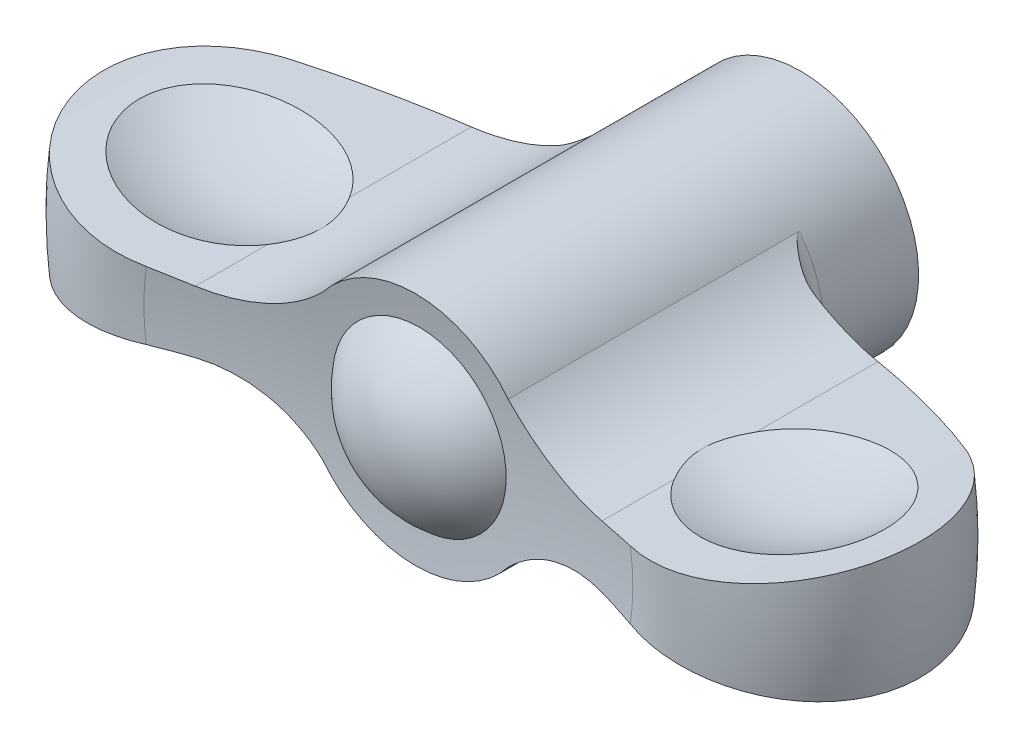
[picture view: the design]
ISO-10303-21;
HEADER;
FILE_DESCRIPTION(('STEP AP214'),'2;1');
FILE_NAME('part.step','',(''),(''),'','','');
FILE_SCHEMA(('AUTOMOTIVE_DESIGN { 1 0 10303 214 1 1 1 1 }'));
ENDSEC;
DATA;
#1=APPLICATION_CONTEXT('core data for automotive mechanical design processes');
#2=APPLICATION_PROTOCOL_DEFINITION('international standard','automotive_design',2000,#1);
#3=PRODUCT_CONTEXT('',#1,'mechanical');
#4=PRODUCT('Part','Part','',(#3));
#5=PRODUCT_RELATED_PRODUCT_CATEGORY('part','',(#4));
#6=PRODUCT_DEFINITION_FORMATION('','',#4);
#7=PRODUCT_DEFINITION_CONTEXT('part definition',#1,'design');
#8=PRODUCT_DEFINITION('design','',#6,#7);
#9=PRODUCT_DEFINITION_SHAPE('','',#8);
#10=(LENGTH_UNIT() NAMED_UNIT(*) SI_UNIT(.MILLI.,.METRE.));
#11=(NAMED_UNIT(*) PLANE_ANGLE_UNIT() SI_UNIT($,.RADIAN.));
#12=(NAMED_UNIT(*) SI_UNIT($,.STERADIAN.) SOLID_ANGLE_UNIT());
#13=UNCERTAINTY_MEASURE_WITH_UNIT(LENGTH_MEASURE(1.E-05),#10,'distance_accuracy_value','');
#14=(GEOMETRIC_REPRESENTATION_CONTEXT(3) GLOBAL_UNCERTAINTY_ASSIGNED_CONTEXT((#13)) GLOBAL_UNIT_ASSIGNED_CONTEXT((#10,
#11,#12)) REPRESENTATION_CONTEXT('',''));
#15=CARTESIAN_POINT('',(0.,0.,0.));
#16=DIRECTION('',(0.,0.,1.));
#17=DIRECTION('',(1.,0.,0.));
#18=AXIS2_PLACEMENT_3D('',#15,#16,#17);
#19=CARTESIAN_POINT('',(0.,0.,8.));
#20=DIRECTION('',(0.,0.,-1.));
#21=DIRECTION('',(0.,1.,0.));
#22=AXIS2_PLACEMENT_3D('',#19,#20,#21);
#23=TOROIDAL_SURFACE('',#22,11.8,1.80000000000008);
#24=CARTESIAN_POINT('',(-10.936400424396,-3.94636818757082,9.7916319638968));
#25=CARTESIAN_POINT('',(-10.824118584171,-4.00370429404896,9.78325234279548));
#26=CARTESIAN_POINT('',(-10.7132133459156,-4.06254400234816,9.76897182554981));
#27=CARTESIAN_POINT('',(-10.4947965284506,-4.18269546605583,9.73031315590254));
#28=CARTESIAN_POINT('',(-10.3872790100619,-4.24400241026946,9.70595387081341));
#29=CARTESIAN_POINT('',(-10.1765147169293,-4.36838152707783,9.6489761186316));
#30=CARTESIAN_POINT('',(-10.0732455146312,-4.43144032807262,9.61641003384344));
#31=CARTESIAN_POINT('',(-9.87034998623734,-4.55941800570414,9.54423053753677));
#32=CARTESIAN_POINT('',(-9.77072514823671,-4.62433762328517,9.50461428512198));
#33=CARTESIAN_POINT('',(-9.55076497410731,-4.77218804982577,9.40879869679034));
#34=CARTESIAN_POINT('',(-9.43146470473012,-4.85557105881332,9.35092807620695));
#35=CARTESIAN_POINT('',(-9.19845422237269,-5.0245357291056,9.22749490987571));
#36=CARTESIAN_POINT('',(-9.08474708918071,-5.11011856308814,9.16192819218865));
#37=CARTESIAN_POINT('',(-8.89583509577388,-5.25740071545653,9.04459290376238));
#38=CARTESIAN_POINT('',(-8.81922141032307,-5.31864764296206,8.99450670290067));
#39=CARTESIAN_POINT('',(-8.66877804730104,-5.44185241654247,8.89113944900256));
#40=CARTESIAN_POINT('',(-8.59494804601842,-5.50381017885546,8.83785876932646));
#41=CARTESIAN_POINT('',(-8.4741799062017,-5.60755853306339,8.74594898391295));
#42=CARTESIAN_POINT('',(-8.42641392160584,-5.64925103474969,8.7082931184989));
#43=CARTESIAN_POINT('',(-8.33242521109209,-5.73256077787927,8.6310972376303));
#44=CARTESIAN_POINT('',(-8.28620142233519,-5.77417805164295,8.59155856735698));
#45=CARTESIAN_POINT('',(-8.21125367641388,-5.84266935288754,8.52388347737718));
#46=CARTESIAN_POINT('',(-8.18198002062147,-5.86968993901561,8.49650386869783));
#47=CARTESIAN_POINT('',(-8.12444979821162,-5.92330159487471,8.44010631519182));
#48=CARTESIAN_POINT('',(-8.09619524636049,-5.94989176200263,8.41108538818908));
#49=CARTESIAN_POINT('',(-8.04234032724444,-6.00103726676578,8.35179046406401));
#50=CARTESIAN_POINT('',(-8.01668026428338,-6.02563150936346,8.32160361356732));
#51=CARTESIAN_POINT('',(-7.96790958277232,-6.07276025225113,8.2576023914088));
#52=CARTESIAN_POINT('',(-7.94479257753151,-6.09529988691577,8.22379754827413));
#53=CARTESIAN_POINT('',(-7.91701322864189,-6.12255630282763,8.17250880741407));
#54=CARTESIAN_POINT('',(-7.90975258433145,-6.12970126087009,8.157793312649));
#55=CARTESIAN_POINT('',(-7.89665438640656,-6.14261741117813,8.12727584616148));
#56=CARTESIAN_POINT('',(-7.89080740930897,-6.14839769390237,8.11148202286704));
#57=CARTESIAN_POINT('',(-7.88158226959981,-6.15753000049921,8.08013275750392));
#58=CARTESIAN_POINT('',(-7.87802903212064,-6.16105398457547,8.06468423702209));
#59=CARTESIAN_POINT('',(-7.87307566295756,-6.16597001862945,8.03281428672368));
#60=CARTESIAN_POINT('',(-7.87172008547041,-6.16731795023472,8.01637956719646));
#61=CARTESIAN_POINT('',(-7.8717856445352,-6.16725149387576,7.9998));
#62=B_SPLINE_CURVE_WITH_KNOTS('',3,(#24,#25,#26,#27,#28,#29,#30,#31,#32,#33,#34,#35,#36,#37,#38,
#39,#40,#41,#42,#43,#44,#45,#46,#47,#48,#49,#50,#51,#52,#53,#54,#55,#56,#57,#58,#59,#60,#61),
.UNSPECIFIED.,.F.,.F.,(4,2,2,2,2,2,2,2,2,2,2,2,2,2,2,2,2,2,4),(0.,0.378686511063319,
0.756667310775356,1.13229407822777,1.50807255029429,1.97761636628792,2.44741590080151,
2.77774393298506,3.10803343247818,3.32923096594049,3.55027276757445,3.6952714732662,
3.84054267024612,3.98039395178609,4.11988557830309,4.17347981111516,4.22670627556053,
4.27513325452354,4.32453026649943),.UNSPECIFIED.);
#63=CARTESIAN_POINT('',(-10.9337221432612,-3.94773654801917,9.7914319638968));
#64=VERTEX_POINT('',#63);
#65=CARTESIAN_POINT('',(-7.8717855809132,-6.16725155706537,8.));
#66=VERTEX_POINT('',#65);
#67=EDGE_CURVE('E487',#64,#66,#62,.T.);
#68=ORIENTED_EDGE('',*,*,#67,.F.);
#69=CARTESIAN_POINT('',(0.,0.,9.7914319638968));
#70=DIRECTION('',(0.,0.,-1.));
#71=DIRECTION('',(0.,1.,0.));
#72=AXIS2_PLACEMENT_3D('',#69,#70,#71);
#73=CIRCLE('',#72,11.6245818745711);
#74=CARTESIAN_POINT('',(-10.9337221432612,3.94773654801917,9.7914319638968));
#75=VERTEX_POINT('',#74);
#76=EDGE_CURVE('E500',#64,#75,#73,.T.);
#77=ORIENTED_EDGE('',*,*,#76,.T.);
#78=CARTESIAN_POINT('',(-10.936400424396,3.94636818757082,9.7916319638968));
#79=CARTESIAN_POINT('',(-10.824118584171,4.00370429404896,9.78325234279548));
#80=CARTESIAN_POINT('',(-10.7132133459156,4.06254400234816,9.76897182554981));
#81=CARTESIAN_POINT('',(-10.4947965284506,4.18269546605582,9.73031315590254));
#82=CARTESIAN_POINT('',(-10.3872790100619,4.24400241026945,9.70595387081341));
#83=CARTESIAN_POINT('',(-10.1765147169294,4.36838152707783,9.64897611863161));
#84=CARTESIAN_POINT('',(-10.0732455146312,4.43144032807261,9.61641003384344));
#85=CARTESIAN_POINT('',(-9.87034998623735,4.55941800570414,9.54423053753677));
#86=CARTESIAN_POINT('',(-9.77072514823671,4.62433762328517,9.50461428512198));
#87=CARTESIAN_POINT('',(-9.55076497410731,4.77218804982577,9.40879869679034));
#88=CARTESIAN_POINT('',(-9.43146470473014,4.85557105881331,9.35092807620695));
#89=CARTESIAN_POINT('',(-9.1984542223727,5.02453572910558,9.22749490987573));
#90=CARTESIAN_POINT('',(-9.0847470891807,5.11011856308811,9.1619281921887));
#91=CARTESIAN_POINT('',(-8.89583509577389,5.25740071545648,9.04459290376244));
#92=CARTESIAN_POINT('',(-8.8192214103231,5.318647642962,8.99450670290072));
#93=CARTESIAN_POINT('',(-8.66877804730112,5.44185241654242,8.89113944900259));
#94=CARTESIAN_POINT('',(-8.59494804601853,5.50381017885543,8.8378587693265));
#95=CARTESIAN_POINT('',(-8.47417990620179,5.60755853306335,8.74594898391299));
#96=CARTESIAN_POINT('',(-8.4264139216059,5.64925103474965,8.70829311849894));
#97=CARTESIAN_POINT('',(-8.33242521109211,5.73256077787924,8.63109723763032));
#98=CARTESIAN_POINT('',(-8.2862014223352,5.77417805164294,8.59155856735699));
#99=CARTESIAN_POINT('',(-8.21125367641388,5.84266935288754,8.52388347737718));
#100=CARTESIAN_POINT('',(-8.18198002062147,5.86968993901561,8.49650386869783));
#101=CARTESIAN_POINT('',(-8.12444979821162,5.92330159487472,8.44010631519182));
#102=CARTESIAN_POINT('',(-8.09619524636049,5.94989176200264,8.41108538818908));
#103=CARTESIAN_POINT('',(-8.04234032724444,6.00103726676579,8.35179046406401));
#104=CARTESIAN_POINT('',(-8.01668026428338,6.02563150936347,8.32160361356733));
#105=CARTESIAN_POINT('',(-7.96790958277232,6.07276025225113,8.2576023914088));
#106=CARTESIAN_POINT('',(-7.94479257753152,6.09529988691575,8.22379754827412));
#107=CARTESIAN_POINT('',(-7.91701322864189,6.12255630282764,8.17250880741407));
#108=CARTESIAN_POINT('',(-7.90975258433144,6.1297012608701,8.15779331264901));
#109=CARTESIAN_POINT('',(-7.89665438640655,6.14261741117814,8.12727584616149));
#110=CARTESIAN_POINT('',(-7.89080740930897,6.14839769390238,8.11148202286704));
#111=CARTESIAN_POINT('',(-7.88158226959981,6.1575300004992,8.08013275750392));
#112=CARTESIAN_POINT('',(-7.87802903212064,6.16105398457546,8.06468423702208));
#113=CARTESIAN_POINT('',(-7.87307566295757,6.16597001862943,8.03281428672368));
#114=CARTESIAN_POINT('',(-7.87172008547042,6.16731795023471,8.01637956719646));
#115=CARTESIAN_POINT('',(-7.8717856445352,6.16725149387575,7.9998));
#116=B_SPLINE_CURVE_WITH_KNOTS('',3,(#78,#79,#80,#81,#82,#83,#84,#85,#86,#87,#88,#89,#90,#91,
#92,#93,#94,#95,#96,#97,#98,#99,#100,#101,#102,#103,#104,#105,#106,#107,#108,#109,#110,#111,
#112,#113,#114,#115),.UNSPECIFIED.,.F.,.F.,(4,2,2,2,2,2,2,2,2,2,2,2,2,2,2,2,2,2,4),(0.,
0.378686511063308,0.756667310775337,1.13229407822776,1.50807255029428,1.97761636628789,
2.44741590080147,2.77774393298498,3.10803343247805,3.32923096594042,3.55027276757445,
3.6952714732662,3.84054267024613,3.98039395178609,4.11988557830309,4.17347981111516,
4.22670627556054,4.27513325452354,4.32453026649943),.UNSPECIFIED.);
#117=CARTESIAN_POINT('',(-7.8717855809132,6.16725155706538,8.));
#118=VERTEX_POINT('',#117);
#119=EDGE_CURVE('E318',#75,#118,#116,.T.);
#120=ORIENTED_EDGE('',*,*,#119,.T.);
#121=CARTESIAN_POINT('',(0.,0.,8.));
#122=DIRECTION('',(0.,0.,-1.));
#123=DIRECTION('',(0.,1.,0.));
#124=AXIS2_PLACEMENT_3D('',#121,#122,#123);
#125=CIRCLE('',#124,10.);
#126=EDGE_CURVE('E437',#66,#118,#125,.T.);
#127=ORIENTED_EDGE('',*,*,#126,.F.);
#128=EDGE_LOOP('',(#68,#77,#120,#127));
#129=FACE_BOUND('',#128,.T.);
#130=ADVANCED_FACE('F14',(#129),#23,.F.);
#131=CARTESIAN_POINT('',(0.,0.,60.3122983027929));
#132=DIRECTION('',(0.,0.,-1.));
#133=DIRECTION('',(0.,1.,0.));
#134=AXIS2_PLACEMENT_3D('',#131,#132,#133);
#135=DEGENERATE_TOROIDAL_SURFACE('',#134,6.6775474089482,50.7624968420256,.T.);
#136=ORIENTED_EDGE('',*,*,#76,.F.);
#137=CARTESIAN_POINT('',(-6.5467060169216,-7.72330133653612,9.66697769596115));
#138=CARTESIAN_POINT('',(-6.64591288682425,-7.58492422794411,9.66416255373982));
#139=CARTESIAN_POINT('',(-6.74799440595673,-7.44862247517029,9.661900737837));
#140=CARTESIAN_POINT('',(-6.95774811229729,-7.18037757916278,9.65844214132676));
#141=CARTESIAN_POINT('',(-7.06542027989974,-7.04843442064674,9.6572453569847));
#142=CARTESIAN_POINT('',(-7.39653737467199,-6.6595102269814,9.65519040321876));
#143=CARTESIAN_POINT('',(-7.62812663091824,-6.40937348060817,9.65586643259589));
#144=CARTESIAN_POINT('',(-8.11129299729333,-5.92925394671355,9.66138002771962));
#145=CARTESIAN_POINT('',(-8.36287299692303,-5.69927408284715,9.66621819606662));
#146=CARTESIAN_POINT('',(-8.88421895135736,-5.26109545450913,9.68055080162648));
#147=CARTESIAN_POINT('',(-9.15398440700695,-5.05289609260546,9.69004511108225));
#148=CARTESIAN_POINT('',(-9.70731186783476,-4.66146851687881,9.71434109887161));
#149=CARTESIAN_POINT('',(-9.99073342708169,-4.47803881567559,9.72909588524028));
#150=CARTESIAN_POINT('',(-10.5714417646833,-4.13530031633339,9.76473262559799));
#151=CARTESIAN_POINT('',(-10.8687285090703,-3.97599145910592,9.78561456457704));
#152=CARTESIAN_POINT('',(-11.4746831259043,-3.68269992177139,9.83420440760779));
#153=CARTESIAN_POINT('',(-11.7833407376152,-3.54869504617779,9.86190627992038));
#154=CARTESIAN_POINT('',(-12.4099583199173,-3.30668939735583,9.92468529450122));
#155=CARTESIAN_POINT('',(-12.72791823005,-3.19868845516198,9.95976238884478));
#156=CARTESIAN_POINT('',(-13.3702784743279,-3.00943594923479,10.0375625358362));
#157=CARTESIAN_POINT('',(-13.694668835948,-2.92814595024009,10.080274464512));
#158=CARTESIAN_POINT('',(-14.3479208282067,-2.7924555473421,10.173495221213));
#159=CARTESIAN_POINT('',(-14.6767824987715,-2.73805538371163,10.2240041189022));
#160=CARTESIAN_POINT('',(-15.3369192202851,-2.65620760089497,10.3328061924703));
#161=CARTESIAN_POINT('',(-15.6681964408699,-2.62878831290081,10.3911074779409));
#162=CARTESIAN_POINT('',(-16.3304789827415,-2.60086726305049,10.5152293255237));
#163=CARTESIAN_POINT('',(-16.6614842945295,-2.60036640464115,10.5810501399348));
#164=CARTESIAN_POINT('',(-17.3240428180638,-2.62605289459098,10.7205107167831));
#165=CARTESIAN_POINT('',(-17.6555720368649,-2.65249066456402,10.7942180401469));
#166=CARTESIAN_POINT('',(-18.3138495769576,-2.73187573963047,10.9484805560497));
#167=CARTESIAN_POINT('',(-18.6405974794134,-2.78482535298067,11.0290363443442));
#168=CARTESIAN_POINT('',(-19.2867879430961,-2.91642655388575,11.1963521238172));
#169=CARTESIAN_POINT('',(-19.6062391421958,-2.99504586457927,11.2831042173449));
#170=CARTESIAN_POINT('',(-20.2362844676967,-3.17708996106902,11.4622866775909));
#171=CARTESIAN_POINT('',(-20.5468805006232,-3.28050936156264,11.5547158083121));
#172=CARTESIAN_POINT('',(-20.8521318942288,-3.39588894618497,11.6496949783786));
#173=B_SPLINE_CURVE_WITH_KNOTS('',3,(#137,#138,#139,#140,#141,#142,#143,#144,#145,#146,#147,
#148,#149,#150,#151,#152,#153,#154,#155,#156,#157,#158,#159,#160,#161,#162,#163,#164,#165,#166,
#167,#168,#169,#170,#171,#172),.UNSPECIFIED.,.F.,.F.,(4,2,2,2,2,2,2,2,2,2,2,2,2,2,2,2,2,4),(0.,
0.510785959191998,1.02157012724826,2.04291399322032,3.06440575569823,4.08586949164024,
5.09844663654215,6.11102130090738,7.12270361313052,8.13437935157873,9.14459291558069,
10.1548155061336,11.1660977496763,12.1774139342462,13.1982178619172,14.2191106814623,
15.2387247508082,16.2581176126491),.UNSPECIFIED.);
#174=CARTESIAN_POINT('',(-17.2513916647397,-2.62600423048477,10.7060191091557));
#175=VERTEX_POINT('',#174);
#176=EDGE_CURVE('E481',#64,#175,#173,.T.);
#177=ORIENTED_EDGE('',*,*,#176,.T.);
#178=CARTESIAN_POINT('',(-28.5420587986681,-3.86093353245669,14.6248916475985));
#179=CARTESIAN_POINT('',(-28.0949251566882,-3.78973654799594,14.4056959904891));
#180=CARTESIAN_POINT('',(-27.6441940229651,-3.72065339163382,14.1932196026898));
#181=CARTESIAN_POINT('',(-26.7359054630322,-3.58698745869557,13.7818878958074));
#182=CARTESIAN_POINT('',(-26.2783480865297,-3.52240464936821,13.583032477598));
#183=CARTESIAN_POINT('',(-24.8998297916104,-3.33633398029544,13.0087706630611));
#184=CARTESIAN_POINT('',(-23.9692804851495,-3.22192463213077,12.6538347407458));
#185=CARTESIAN_POINT('',(-22.0863023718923,-3.01405683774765,12.0002442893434));
#186=CARTESIAN_POINT('',(-21.133873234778,-2.92059870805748,11.701590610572));
#187=CARTESIAN_POINT('',(-19.6898454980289,-2.79722984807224,11.296179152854));
#188=CARTESIAN_POINT('',(-19.2049108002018,-2.75884755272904,11.1679139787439));
#189=CARTESIAN_POINT('',(-18.2309836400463,-2.68796520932,10.9259763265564));
#190=CARTESIAN_POINT('',(-17.7419911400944,-2.65546521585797,10.8123039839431));
#191=CARTESIAN_POINT('',(-17.2511916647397,-2.6259922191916,10.7059757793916));
#192=B_SPLINE_CURVE_WITH_KNOTS('',3,(#178,#179,#180,#181,#182,#183,#184,#185,#186,#187,#188,
#189,#190,#191),.UNSPECIFIED.,.F.,.F.,(4,2,2,2,2,2,4),(0.,1.50898291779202,3.01795485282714,
6.0232908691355,9.02867228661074,10.5376740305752,12.0466897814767),.UNSPECIFIED.);
#193=CARTESIAN_POINT('',(-28.5416508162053,-3.86086857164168,14.6246916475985));
#194=VERTEX_POINT('',#193);
#195=EDGE_CURVE('E511',#194,#175,#192,.T.);
#196=ORIENTED_EDGE('',*,*,#195,.F.);
#197=CARTESIAN_POINT('',(0.,0.,14.6246916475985));
#198=DIRECTION('',(0.,0.,-1.));
#199=DIRECTION('',(0.,1.,0.));
#200=AXIS2_PLACEMENT_3D('',#197,#198,#199);
#201=CIRCLE('',#200,28.8015995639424);
#202=CARTESIAN_POINT('',(-28.5416508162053,3.86086857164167,14.6246916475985));
#203=VERTEX_POINT('',#202);
#204=EDGE_CURVE('E498',#194,#203,#201,.T.);
#205=ORIENTED_EDGE('',*,*,#204,.T.);
#206=CARTESIAN_POINT('',(-28.542058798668,3.86093353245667,14.6248916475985));
#207=CARTESIAN_POINT('',(-28.0949251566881,3.78973654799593,14.4056959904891));
#208=CARTESIAN_POINT('',(-27.644194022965,3.7206533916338,14.1932196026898));
#209=CARTESIAN_POINT('',(-26.7359054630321,3.58698745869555,13.7818878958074));
#210=CARTESIAN_POINT('',(-26.2783480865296,3.52240464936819,13.583032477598));
#211=CARTESIAN_POINT('',(-24.8998297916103,3.33633398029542,13.0087706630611));
#212=CARTESIAN_POINT('',(-23.9692804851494,3.22192463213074,12.6538347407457));
#213=CARTESIAN_POINT('',(-22.0863023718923,3.01405683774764,12.0002442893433));
#214=CARTESIAN_POINT('',(-21.133873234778,2.92059870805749,11.701590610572));
#215=CARTESIAN_POINT('',(-19.6898454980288,2.79722984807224,11.296179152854));
#216=CARTESIAN_POINT('',(-19.2049108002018,2.75884755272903,11.1679139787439));
#217=CARTESIAN_POINT('',(-18.2309836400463,2.68796520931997,10.9259763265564));
#218=CARTESIAN_POINT('',(-17.7419911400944,2.65546521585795,10.8123039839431));
#219=CARTESIAN_POINT('',(-17.2511916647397,2.6259922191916,10.7059757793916));
#220=B_SPLINE_CURVE_WITH_KNOTS('',3,(#206,#207,#208,#209,#210,#211,#212,#213,#214,#215,#216,
#217,#218,#219),.UNSPECIFIED.,.F.,.F.,(4,2,2,2,2,2,4),(0.,1.50898291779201,3.01795485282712,
6.02329086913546,9.02867228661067,10.5376740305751,12.0466897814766),.UNSPECIFIED.);
#221=CARTESIAN_POINT('',(-17.2513916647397,2.62600423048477,10.7060191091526));
#222=VERTEX_POINT('',#221);
#223=EDGE_CURVE('E332',#203,#222,#220,.T.);
#224=ORIENTED_EDGE('',*,*,#223,.T.);
#225=CARTESIAN_POINT('',(-6.5467060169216,7.72330133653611,9.66697769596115));
#226=CARTESIAN_POINT('',(-6.64591288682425,7.5849242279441,9.66416255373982));
#227=CARTESIAN_POINT('',(-6.74799440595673,7.44862247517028,9.661900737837));
#228=CARTESIAN_POINT('',(-6.9577481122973,7.18037757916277,9.65844214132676));
#229=CARTESIAN_POINT('',(-7.06542027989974,7.04843442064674,9.6572453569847));
#230=CARTESIAN_POINT('',(-7.39653737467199,6.65951022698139,9.65519040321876));
#231=CARTESIAN_POINT('',(-7.62812663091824,6.40937348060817,9.65586643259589));
#232=CARTESIAN_POINT('',(-8.11129299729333,5.92925394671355,9.66138002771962));
#233=CARTESIAN_POINT('',(-8.36287299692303,5.69927408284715,9.66621819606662));
#234=CARTESIAN_POINT('',(-8.88421895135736,5.26109545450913,9.68055080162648));
#235=CARTESIAN_POINT('',(-9.15398440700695,5.05289609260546,9.69004511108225));
#236=CARTESIAN_POINT('',(-9.70731186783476,4.66146851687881,9.71434109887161));
#237=CARTESIAN_POINT('',(-9.99073342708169,4.47803881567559,9.72909588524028));
#238=CARTESIAN_POINT('',(-10.5714417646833,4.13530031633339,9.76473262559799));
#239=CARTESIAN_POINT('',(-10.8687285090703,3.97599145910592,9.78561456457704));
#240=CARTESIAN_POINT('',(-11.4746831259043,3.68269992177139,9.83420440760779));
#241=CARTESIAN_POINT('',(-11.7833407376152,3.54869504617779,9.86190627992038));
#242=CARTESIAN_POINT('',(-12.4099583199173,3.30668939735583,9.92468529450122));
#243=CARTESIAN_POINT('',(-12.72791823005,3.19868845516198,9.95976238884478));
#244=CARTESIAN_POINT('',(-13.3702784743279,3.00943594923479,10.0375625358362));
#245=CARTESIAN_POINT('',(-13.694668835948,2.92814595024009,10.080274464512));
#246=CARTESIAN_POINT('',(-14.3479208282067,2.7924555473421,10.173495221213));
#247=CARTESIAN_POINT('',(-14.6767824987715,2.73805538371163,10.2240041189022));
#248=CARTESIAN_POINT('',(-15.3369192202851,2.65620760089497,10.3328061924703));
#249=CARTESIAN_POINT('',(-15.6681964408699,2.62878831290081,10.3911074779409));
#250=CARTESIAN_POINT('',(-16.3304789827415,2.60086726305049,10.5152293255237));
#251=CARTESIAN_POINT('',(-16.6614842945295,2.60036640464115,10.5810501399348));
#252=CARTESIAN_POINT('',(-17.3240428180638,2.62605289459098,10.7205107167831));
#253=CARTESIAN_POINT('',(-17.6555720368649,2.65249066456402,10.7942180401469));
#254=CARTESIAN_POINT('',(-18.3138495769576,2.73187573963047,10.9484805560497));
#255=CARTESIAN_POINT('',(-18.6405974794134,2.78482535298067,11.0290363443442));
#256=CARTESIAN_POINT('',(-19.2867879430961,2.91642655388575,11.1963521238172));
#257=CARTESIAN_POINT('',(-19.6062391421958,2.99504586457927,11.2831042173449));
#258=CARTESIAN_POINT('',(-20.2362844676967,3.17708996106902,11.4622866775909));
#259=CARTESIAN_POINT('',(-20.5468805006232,3.28050936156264,11.5547158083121));
#260=CARTESIAN_POINT('',(-20.8521318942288,3.39588894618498,11.6496949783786));
#261=B_SPLINE_CURVE_WITH_KNOTS('',3,(#225,#226,#227,#228,#229,#230,#231,#232,#233,#234,#235,
#236,#237,#238,#239,#240,#241,#242,#243,#244,#245,#246,#247,#248,#249,#250,#251,#252,#253,#254,
#255,#256,#257,#258,#259,#260),.UNSPECIFIED.,.F.,.F.,(4,2,2,2,2,2,2,2,2,2,2,2,2,2,2,2,2,4),(0.,
0.510785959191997,1.02157012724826,2.04291399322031,3.06440575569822,4.08586949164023,
5.09844663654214,6.11102130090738,7.12270361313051,8.13437935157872,9.14459291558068,
10.1548155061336,11.1660977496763,12.1774139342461,13.1982178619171,14.2191106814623,
15.2387247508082,16.2581176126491),.UNSPECIFIED.);
#262=EDGE_CURVE('E301',#75,#222,#261,.T.);
#263=ORIENTED_EDGE('',*,*,#262,.F.);
#264=EDGE_LOOP('',(#136,#177,#196,#205,#224,#263));
#265=FACE_BOUND('',#264,.T.);
#266=ADVANCED_FACE('F508',(#265),#135,.T.);
#267=CARTESIAN_POINT('',(0.,0.,24.5131504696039));
#268=DIRECTION('',(0.,0.,-1.));
#269=DIRECTION('',(0.,1.,0.));
#270=AXIS2_PLACEMENT_3D('',#267,#268,#269);
#271=TOROIDAL_SURFACE('',#270,24.0131504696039,10.9868495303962);
#272=CARTESIAN_POINT('',(-17.2511916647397,-2.62599221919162,33.3242100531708));
#273=CARTESIAN_POINT('',(-17.4993781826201,-2.64089075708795,33.5086851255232));
#274=CARTESIAN_POINT('',(-17.7552628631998,-2.65706460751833,33.6826969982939));
#275=CARTESIAN_POINT('',(-18.28053769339,-2.69210530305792,34.0086627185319));
#276=CARTESIAN_POINT('',(-18.5499277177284,-2.71097212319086,34.1606167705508));
#277=CARTESIAN_POINT('',(-19.1002002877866,-2.75153205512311,34.4412740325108));
#278=CARTESIAN_POINT('',(-19.381077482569,-2.77322386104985,34.5699879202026));
#279=CARTESIAN_POINT('',(-19.952432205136,-2.81952002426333,34.8033129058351));
#280=CARTESIAN_POINT('',(-20.2429095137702,-2.84412431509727,34.9079245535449));
#281=CARTESIAN_POINT('',(-20.8315983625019,-2.89628797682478,35.0923323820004));
#282=CARTESIAN_POINT('',(-21.1298150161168,-2.92384934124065,35.1721116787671));
#283=CARTESIAN_POINT('',(-21.7316508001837,-2.98187199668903,35.3061577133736));
#284=CARTESIAN_POINT('',(-22.035269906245,-3.01233327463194,35.3604245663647));
#285=CARTESIAN_POINT('',(-22.6456357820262,-3.0760359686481,35.4430189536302));
#286=CARTESIAN_POINT('',(-22.9523815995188,-3.10927655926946,35.4713541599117));
#287=CARTESIAN_POINT('',(-23.566877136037,-3.17836345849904,35.501889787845));
#288=CARTESIAN_POINT('',(-23.874626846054,-3.21420974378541,35.504090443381));
#289=CARTESIAN_POINT('',(-24.4874432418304,-3.28807700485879,35.4823817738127));
#290=CARTESIAN_POINT('',(-24.7925157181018,-3.32608674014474,35.4585974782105));
#291=CARTESIAN_POINT('',(-25.3992908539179,-3.404117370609,35.3852808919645));
#292=CARTESIAN_POINT('',(-25.7009935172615,-3.44413826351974,35.3357486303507));
#293=CARTESIAN_POINT('',(-26.2989412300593,-3.52581537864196,35.211278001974));
#294=CARTESIAN_POINT('',(-26.595185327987,-3.56747188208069,35.1363352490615));
#295=CARTESIAN_POINT('',(-27.1800717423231,-3.65197221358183,34.9615826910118));
#296=CARTESIAN_POINT('',(-27.4687140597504,-3.69481604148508,34.8617728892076));
#297=CARTESIAN_POINT('',(-28.035952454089,-3.78113479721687,34.6381665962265));
#298=CARTESIAN_POINT('',(-28.3145627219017,-3.82460870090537,34.514405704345));
#299=CARTESIAN_POINT('',(-28.8602471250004,-3.9117173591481,34.2436848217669));
#300=CARTESIAN_POINT('',(-29.1273212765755,-3.9553521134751,34.0967248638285));
#301=CARTESIAN_POINT('',(-29.6480727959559,-4.04221651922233,33.7806574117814));
#302=CARTESIAN_POINT('',(-29.9017509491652,-4.08544619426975,33.6115512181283));
#303=CARTESIAN_POINT('',(-30.3939845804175,-4.17091924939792,33.2523788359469));
#304=CARTESIAN_POINT('',(-30.6325400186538,-4.21316262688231,33.0623125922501));
#305=CARTESIAN_POINT('',(-31.0935716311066,-4.29619199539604,32.6619711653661));
#306=CARTESIAN_POINT('',(-31.3159985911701,-4.33697334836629,32.4516383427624));
#307=CARTESIAN_POINT('',(-31.7424740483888,-4.41635307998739,32.0127202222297));
#308=CARTESIAN_POINT('',(-31.9465225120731,-4.45495145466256,31.7841348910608));
#309=CARTESIAN_POINT('',(-32.3348520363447,-4.5293877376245,31.3103146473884));
#310=CARTESIAN_POINT('',(-32.5191323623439,-4.56522554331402,31.0650791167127));
#311=CARTESIAN_POINT('',(-32.8666572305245,-4.63358841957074,30.5596945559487));
#312=CARTESIAN_POINT('',(-33.0299017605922,-4.66611348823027,30.2995455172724));
#313=CARTESIAN_POINT('',(-33.3345075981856,-4.72739462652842,29.7656976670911));
#314=CARTESIAN_POINT('',(-33.4758297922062,-4.75614394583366,29.4919757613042));
#315=CARTESIAN_POINT('',(-33.7352733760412,-4.80934524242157,28.9333467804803));
#316=CARTESIAN_POINT('',(-33.8533947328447,-4.83379721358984,28.6484396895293));
#317=CARTESIAN_POINT('',(-34.0656204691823,-4.87800530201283,28.0694731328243));
#318=CARTESIAN_POINT('',(-34.1597255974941,-4.89776156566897,27.7754139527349));
#319=CARTESIAN_POINT('',(-34.3232748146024,-4.93225390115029,27.180228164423));
#320=CARTESIAN_POINT('',(-34.3927189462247,-4.94698998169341,26.8791015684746));
#321=CARTESIAN_POINT('',(-34.5063857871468,-4.97117989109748,26.2723608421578));
#322=CARTESIAN_POINT('',(-34.5506442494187,-4.98064120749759,25.96675370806));
#323=CARTESIAN_POINT('',(-34.6137870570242,-4.99415603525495,25.3528106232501));
#324=CARTESIAN_POINT('',(-34.6326714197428,-4.99820955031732,25.0444746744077));
#325=CARTESIAN_POINT('',(-34.644935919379,-5.00084099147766,24.4272603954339));
#326=CARTESIAN_POINT('',(-34.6383150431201,-4.99941870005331,24.1183820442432));
#327=CARTESIAN_POINT('',(-34.5996125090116,-4.9911218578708,23.5022985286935));
#328=CARTESIAN_POINT('',(-34.5675308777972,-4.9842473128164,23.1950933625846));
#329=CARTESIAN_POINT('',(-34.4781950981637,-4.96517513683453,22.5850017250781));
#330=CARTESIAN_POINT('',(-34.4209785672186,-4.95298546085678,22.2821094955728));
#331=CARTESIAN_POINT('',(-34.2817747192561,-4.92348679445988,21.6823260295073));
#332=CARTESIAN_POINT('',(-34.1997873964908,-4.90617780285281,21.3854347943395));
#333=CARTESIAN_POINT('',(-34.0116119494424,-4.86672680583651,20.799780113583));
#334=CARTESIAN_POINT('',(-33.9054257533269,-4.84458518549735,20.5110160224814));
#335=CARTESIAN_POINT('',(-33.6695763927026,-4.79582854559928,19.9436331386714));
#336=CARTESIAN_POINT('',(-33.5399133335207,-4.76921354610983,19.6650143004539));
#337=CARTESIAN_POINT('',(-33.2578321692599,-4.71190410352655,19.1195687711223));
#338=CARTESIAN_POINT('',(-33.1053878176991,-4.68120495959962,18.8527561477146));
#339=CARTESIAN_POINT('',(-32.7788934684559,-4.61623623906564,18.3331441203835));
#340=CARTESIAN_POINT('',(-32.6048429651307,-4.58196657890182,18.0803450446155));
#341=CARTESIAN_POINT('',(-32.2363296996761,-4.51038975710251,17.5905487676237));
#342=CARTESIAN_POINT('',(-32.0418667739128,-4.47308257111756,17.3535516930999));
#343=CARTESIAN_POINT('',(-31.633867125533,-4.39599896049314,16.8970435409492));
#344=CARTESIAN_POINT('',(-31.4203320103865,-4.35622274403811,16.6775309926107));
#345=CARTESIAN_POINT('',(-31.0011481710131,-4.27945832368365,16.2816097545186));
#346=CARTESIAN_POINT('',(-30.797399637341,-4.24267293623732,16.103144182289));
#347=CARTESIAN_POINT('',(-30.377205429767,-4.16804353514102,15.7621159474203));
#348=CARTESIAN_POINT('',(-30.1607608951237,-4.13019961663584,15.5995518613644));
#349=CARTESIAN_POINT('',(-29.7163820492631,-4.05387450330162,15.2912603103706));
#350=CARTESIAN_POINT('',(-29.4884504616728,-4.01539346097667,15.1455288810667));
#351=CARTESIAN_POINT('',(-29.0222683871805,-3.9381829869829,14.871631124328));
#352=CARTESIAN_POINT('',(-28.7840165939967,-3.89945352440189,14.7434670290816));
#353=CARTESIAN_POINT('',(-28.5412428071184,-3.86080360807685,14.6244916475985));
#354=B_SPLINE_CURVE_WITH_KNOTS('',3,(#272,#273,#274,#275,#276,#277,#278,#279,#280,#281,#282,
#283,#284,#285,#286,#287,#288,#289,#290,#291,#292,#293,#294,#295,#296,#297,#298,#299,#300,#301,
#302,#303,#304,#305,#306,#307,#308,#309,#310,#311,#312,#313,#314,#315,#316,#317,#318,#319,#320,
#321,#322,#323,#324,#325,#326,#327,#328,#329,#330,#331,#332,#333,#334,#335,#336,#337,#338,#339,
#340,#341,#342,#343,#344,#345,#346,#347,#348,#349,#350,#351,#352,#353),.UNSPECIFIED.,.F.,.F.,(4,
2,2,2,2,2,2,2,2,2,2,2,2,2,2,2,2,2,2,2,2,2,2,2,2,2,2,2,2,2,2,2,2,2,2,2,2,2,2,2,4),(0.,
0.928513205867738,1.85701780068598,2.7850947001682,3.7131504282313,4.64183578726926,
5.57051695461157,6.49892327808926,7.42732129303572,8.35127181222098,9.27522128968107,
10.1993303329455,11.1234392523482,12.0461850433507,12.9689295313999,13.8916198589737,
14.8143126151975,15.7397117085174,16.6651124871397,17.5905476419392,18.5159833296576,
19.4430516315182,20.3701212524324,21.2971619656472,22.2242010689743,23.1499208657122,
24.0756400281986,25.0013959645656,25.9271509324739,26.8515250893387,27.7758994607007,
28.7002002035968,29.6244967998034,30.5498666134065,31.4752580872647,32.4006569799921,
33.3259779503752,34.1452666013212,34.9644818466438,35.7835037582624,36.6026296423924),.UNSPECIFIED.);
#355=CARTESIAN_POINT('',(-20.5453214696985,-2.87092129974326,35.0026521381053));
#356=VERTEX_POINT('',#355);
#357=EDGE_CURVE('E514',#356,#194,#354,.T.);
#358=ORIENTED_EDGE('',*,*,#357,.F.);
#359=CARTESIAN_POINT('',(0.,0.,35.0026521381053));
#360=DIRECTION('',(0.,0.,-1.));
#361=DIRECTION('',(0.,1.,0.));
#362=AXIS2_PLACEMENT_3D('',#359,#360,#361);
#363=CIRCLE('',#362,20.7449372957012);
#364=CARTESIAN_POINT('',(-20.5453214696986,2.87092129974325,35.0026521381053));
#365=VERTEX_POINT('',#364);
#366=EDGE_CURVE('E496',#356,#365,#363,.T.);
#367=ORIENTED_EDGE('',*,*,#366,.T.);
#368=CARTESIAN_POINT('',(-17.2511916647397,2.6259922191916,33.3242100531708));
#369=CARTESIAN_POINT('',(-17.4993781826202,2.64089075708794,33.5086851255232));
#370=CARTESIAN_POINT('',(-17.7552628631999,2.65706460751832,33.6826969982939));
#371=CARTESIAN_POINT('',(-18.28053769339,2.69210530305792,34.0086627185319));
#372=CARTESIAN_POINT('',(-18.5499277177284,2.71097212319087,34.1606167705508));
#373=CARTESIAN_POINT('',(-19.1002002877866,2.75153205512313,34.4412740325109));
#374=CARTESIAN_POINT('',(-19.3810774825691,2.77322386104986,34.5699879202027));
#375=CARTESIAN_POINT('',(-19.952432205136,2.81952002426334,34.8033129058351));
#376=CARTESIAN_POINT('',(-20.2429095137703,2.84412431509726,34.9079245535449));
#377=CARTESIAN_POINT('',(-20.831598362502,2.89628797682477,35.0923323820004));
#378=CARTESIAN_POINT('',(-21.1298150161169,2.92384934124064,35.1721116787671));
#379=CARTESIAN_POINT('',(-21.7316508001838,2.98187199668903,35.3061577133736));
#380=CARTESIAN_POINT('',(-22.0352699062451,3.01233327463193,35.3604245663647));
#381=CARTESIAN_POINT('',(-22.6456357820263,3.0760359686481,35.4430189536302));
#382=CARTESIAN_POINT('',(-22.9523815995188,3.10927655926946,35.4713541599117));
#383=CARTESIAN_POINT('',(-23.566877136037,3.17836345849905,35.501889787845));
#384=CARTESIAN_POINT('',(-23.874626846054,3.21420974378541,35.504090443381));
#385=CARTESIAN_POINT('',(-24.4874432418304,3.28807700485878,35.4823817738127));
#386=CARTESIAN_POINT('',(-24.7925157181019,3.32608674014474,35.4585974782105));
#387=CARTESIAN_POINT('',(-25.3992908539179,3.404117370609,35.3852808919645));
#388=CARTESIAN_POINT('',(-25.7009935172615,3.44413826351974,35.3357486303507));
#389=CARTESIAN_POINT('',(-26.2989412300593,3.52581537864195,35.211278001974));
#390=CARTESIAN_POINT('',(-26.595185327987,3.56747188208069,35.1363352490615));
#391=CARTESIAN_POINT('',(-27.1800717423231,3.65197221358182,34.9615826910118));
#392=CARTESIAN_POINT('',(-27.4687140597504,3.69481604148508,34.8617728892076));
#393=CARTESIAN_POINT('',(-28.035952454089,3.78113479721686,34.6381665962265));
#394=CARTESIAN_POINT('',(-28.3145627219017,3.82460870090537,34.514405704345));
#395=CARTESIAN_POINT('',(-28.8602471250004,3.9117173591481,34.2436848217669));
#396=CARTESIAN_POINT('',(-29.1273212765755,3.9553521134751,34.0967248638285));
#397=CARTESIAN_POINT('',(-29.6480727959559,4.04221651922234,33.7806574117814));
#398=CARTESIAN_POINT('',(-29.9017509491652,4.08544619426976,33.6115512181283));
#399=CARTESIAN_POINT('',(-30.3939845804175,4.17091924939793,33.2523788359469));
#400=CARTESIAN_POINT('',(-30.6325400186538,4.21316262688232,33.0623125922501));
#401=CARTESIAN_POINT('',(-31.0935716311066,4.29619199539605,32.6619711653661));
#402=CARTESIAN_POINT('',(-31.3159985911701,4.33697334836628,32.4516383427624));
#403=CARTESIAN_POINT('',(-31.7424740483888,4.41635307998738,32.0127202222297));
#404=CARTESIAN_POINT('',(-31.9465225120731,4.45495145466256,31.7841348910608));
#405=CARTESIAN_POINT('',(-32.3348520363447,4.52938773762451,31.3103146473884));
#406=CARTESIAN_POINT('',(-32.5191323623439,4.56522554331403,31.0650791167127));
#407=CARTESIAN_POINT('',(-32.8666572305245,4.63358841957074,30.5596945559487));
#408=CARTESIAN_POINT('',(-33.0299017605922,4.66611348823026,30.2995455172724));
#409=CARTESIAN_POINT('',(-33.3345075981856,4.72739462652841,29.7656976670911));
#410=CARTESIAN_POINT('',(-33.4758297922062,4.75614394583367,29.4919757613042));
#411=CARTESIAN_POINT('',(-33.7352733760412,4.80934524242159,28.9333467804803));
#412=CARTESIAN_POINT('',(-33.8533947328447,4.83379721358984,28.6484396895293));
#413=CARTESIAN_POINT('',(-34.0656204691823,4.87800530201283,28.0694731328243));
#414=CARTESIAN_POINT('',(-34.1597255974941,4.89776156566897,27.7754139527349));
#415=CARTESIAN_POINT('',(-34.3232748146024,4.93225390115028,27.180228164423));
#416=CARTESIAN_POINT('',(-34.3927189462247,4.9469899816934,26.8791015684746));
#417=CARTESIAN_POINT('',(-34.5063857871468,4.97117989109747,26.2723608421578));
#418=CARTESIAN_POINT('',(-34.5506442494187,4.9806412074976,25.96675370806));
#419=CARTESIAN_POINT('',(-34.6137870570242,4.99415603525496,25.3528106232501));
#420=CARTESIAN_POINT('',(-34.6326714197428,4.99820955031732,25.0444746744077));
#421=CARTESIAN_POINT('',(-34.644935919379,5.00084099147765,24.4272603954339));
#422=CARTESIAN_POINT('',(-34.6383150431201,4.9994187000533,24.1183820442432));
#423=CARTESIAN_POINT('',(-34.5996125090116,4.99112185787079,23.5022985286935));
#424=CARTESIAN_POINT('',(-34.5675308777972,4.98424731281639,23.1950933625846));
#425=CARTESIAN_POINT('',(-34.4781950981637,4.96517513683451,22.5850017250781));
#426=CARTESIAN_POINT('',(-34.4209785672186,4.95298546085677,22.2821094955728));
#427=CARTESIAN_POINT('',(-34.2817747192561,4.92348679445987,21.6823260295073));
#428=CARTESIAN_POINT('',(-34.1997873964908,4.90617780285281,21.3854347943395));
#429=CARTESIAN_POINT('',(-34.0116119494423,4.86672680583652,20.7997801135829));
#430=CARTESIAN_POINT('',(-33.9054257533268,4.84458518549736,20.5110160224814));
#431=CARTESIAN_POINT('',(-33.6695763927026,4.79582854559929,19.9436331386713));
#432=CARTESIAN_POINT('',(-33.5399133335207,4.76921354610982,19.6650143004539));
#433=CARTESIAN_POINT('',(-33.2578321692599,4.71190410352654,19.1195687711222));
#434=CARTESIAN_POINT('',(-33.1053878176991,4.68120495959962,18.8527561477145));
#435=CARTESIAN_POINT('',(-32.7788934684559,4.61623623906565,18.3331441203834));
#436=CARTESIAN_POINT('',(-32.6048429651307,4.58196657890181,18.0803450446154));
#437=CARTESIAN_POINT('',(-32.2363296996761,4.5103897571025,17.5905487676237));
#438=CARTESIAN_POINT('',(-32.0418667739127,4.47308257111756,17.3535516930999));
#439=CARTESIAN_POINT('',(-31.633867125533,4.39599896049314,16.8970435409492));
#440=CARTESIAN_POINT('',(-31.4203320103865,4.3562227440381,16.6775309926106));
#441=CARTESIAN_POINT('',(-31.0011481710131,4.27945832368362,16.2816097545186));
#442=CARTESIAN_POINT('',(-30.797399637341,4.2426729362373,16.103144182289));
#443=CARTESIAN_POINT('',(-30.377205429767,4.16804353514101,15.7621159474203));
#444=CARTESIAN_POINT('',(-30.1607608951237,4.13019961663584,15.5995518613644));
#445=CARTESIAN_POINT('',(-29.7163820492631,4.05387450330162,15.2912603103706));
#446=CARTESIAN_POINT('',(-29.4884504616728,4.01539346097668,15.1455288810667));
#447=CARTESIAN_POINT('',(-29.0222683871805,3.93818298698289,14.871631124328));
#448=CARTESIAN_POINT('',(-28.7840165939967,3.89945352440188,14.7434670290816));
#449=CARTESIAN_POINT('',(-28.5412428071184,3.86080360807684,14.6244916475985));
#450=B_SPLINE_CURVE_WITH_KNOTS('',3,(#368,#369,#370,#371,#372,#373,#374,#375,#376,#377,#378,
#379,#380,#381,#382,#383,#384,#385,#386,#387,#388,#389,#390,#391,#392,#393,#394,#395,#396,#397,
#398,#399,#400,#401,#402,#403,#404,#405,#406,#407,#408,#409,#410,#411,#412,#413,#414,#415,#416,
#417,#418,#419,#420,#421,#422,#423,#424,#425,#426,#427,#428,#429,#430,#431,#432,#433,#434,#435,
#436,#437,#438,#439,#440,#441,#442,#443,#444,#445,#446,#447,#448,#449),.UNSPECIFIED.,.F.,.F.,(4,
2,2,2,2,2,2,2,2,2,2,2,2,2,2,2,2,2,2,2,2,2,2,2,2,2,2,2,2,2,2,2,2,2,2,2,2,2,2,2,4),(0.,
0.92851320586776,1.85701780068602,2.78509470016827,3.7131504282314,4.64183578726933,
5.57051695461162,6.49892327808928,7.42732129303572,8.35127181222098,9.27522128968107,
10.1993303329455,11.1234392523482,12.0461850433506,12.9689295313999,13.8916198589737,
14.8143126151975,15.7397117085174,16.6651124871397,17.5905476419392,18.5159833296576,
19.4430516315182,20.3701212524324,21.2971619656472,22.2242010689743,23.1499208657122,
24.0756400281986,25.0013959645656,25.9271509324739,26.8515250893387,27.7758994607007,
28.7002002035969,29.6244967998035,30.5498666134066,31.4752580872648,32.4006569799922,
33.3259779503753,34.1452666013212,34.9644818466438,35.7835037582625,36.6026296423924),.UNSPECIFIED.);
#451=EDGE_CURVE('E325',#365,#203,#450,.T.);
#452=ORIENTED_EDGE('',*,*,#451,.T.);
#453=ORIENTED_EDGE('',*,*,#204,.F.);
#454=EDGE_LOOP('',(#358,#367,#452,#453));
#455=FACE_BOUND('',#454,.T.);
#456=ADVANCED_FACE('F338',(#455),#271,.T.);
#457=CARTESIAN_POINT('',(17.2511916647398,2.6259922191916,33.3242100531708));
#458=CARTESIAN_POINT('',(17.4993781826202,2.64089075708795,33.5086851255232));
#459=CARTESIAN_POINT('',(17.7552628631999,2.65706460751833,33.6826969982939));
#460=CARTESIAN_POINT('',(18.28053769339,2.69210530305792,34.0086627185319));
#461=CARTESIAN_POINT('',(18.5499277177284,2.71097212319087,34.1606167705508));
#462=CARTESIAN_POINT('',(19.1002002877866,2.75153205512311,34.4412740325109));
#463=CARTESIAN_POINT('',(19.3810774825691,2.77322386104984,34.5699879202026));
#464=CARTESIAN_POINT('',(19.952432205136,2.81952002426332,34.8033129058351));
#465=CARTESIAN_POINT('',(20.2429095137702,2.84412431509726,34.9079245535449));
#466=CARTESIAN_POINT('',(20.8315983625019,2.89628797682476,35.0923323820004));
#467=CARTESIAN_POINT('',(21.1298150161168,2.92384934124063,35.1721116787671));
#468=CARTESIAN_POINT('',(21.7316508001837,2.98187199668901,35.3061577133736));
#469=CARTESIAN_POINT('',(22.035269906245,3.01233327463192,35.3604245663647));
#470=CARTESIAN_POINT('',(22.6456357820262,3.07603596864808,35.4430189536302));
#471=CARTESIAN_POINT('',(22.9523815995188,3.10927655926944,35.4713541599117));
#472=CARTESIAN_POINT('',(23.566877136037,3.17836345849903,35.501889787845));
#473=CARTESIAN_POINT('',(23.874626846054,3.21420974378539,35.504090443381));
#474=CARTESIAN_POINT('',(24.4874432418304,3.28807700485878,35.4823817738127));
#475=CARTESIAN_POINT('',(24.7925157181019,3.32608674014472,35.4585974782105));
#476=CARTESIAN_POINT('',(25.3992908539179,3.40411737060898,35.3852808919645));
#477=CARTESIAN_POINT('',(25.7009935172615,3.44413826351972,35.3357486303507));
#478=CARTESIAN_POINT('',(26.2989412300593,3.52581537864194,35.211278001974));
#479=CARTESIAN_POINT('',(26.595185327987,3.56747188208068,35.1363352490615));
#480=CARTESIAN_POINT('',(27.1800717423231,3.65197221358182,34.9615826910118));
#481=CARTESIAN_POINT('',(27.4687140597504,3.69481604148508,34.8617728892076));
#482=CARTESIAN_POINT('',(28.035952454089,3.78113479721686,34.6381665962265));
#483=CARTESIAN_POINT('',(28.3145627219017,3.82460870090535,34.514405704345));
#484=CARTESIAN_POINT('',(28.8602471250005,3.91171735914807,34.2436848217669));
#485=CARTESIAN_POINT('',(29.1273212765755,3.95535211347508,34.0967248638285));
#486=CARTESIAN_POINT('',(29.6480727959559,4.04221651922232,33.7806574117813));
#487=CARTESIAN_POINT('',(29.9017509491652,4.08544619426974,33.6115512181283));
#488=CARTESIAN_POINT('',(30.3939845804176,4.17091924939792,33.2523788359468));
#489=CARTESIAN_POINT('',(30.6325400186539,4.21316262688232,33.0623125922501));
#490=CARTESIAN_POINT('',(31.0935716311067,4.29619199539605,32.6619711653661));
#491=CARTESIAN_POINT('',(31.3159985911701,4.33697334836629,32.4516383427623));
#492=CARTESIAN_POINT('',(31.7424740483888,4.41635307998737,32.0127202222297));
#493=CARTESIAN_POINT('',(31.9465225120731,4.45495145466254,31.7841348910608));
#494=CARTESIAN_POINT('',(32.3348520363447,4.52938773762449,31.3103146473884));
#495=CARTESIAN_POINT('',(32.5191323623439,4.56522554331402,31.0650791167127));
#496=CARTESIAN_POINT('',(32.8666572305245,4.63358841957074,30.5596945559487));
#497=CARTESIAN_POINT('',(33.0299017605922,4.66611348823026,30.2995455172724));
#498=CARTESIAN_POINT('',(33.3345075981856,4.72739462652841,29.7656976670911));
#499=CARTESIAN_POINT('',(33.4758297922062,4.75614394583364,29.4919757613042));
#500=CARTESIAN_POINT('',(33.7352733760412,4.80934524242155,28.9333467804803));
#501=CARTESIAN_POINT('',(33.8533947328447,4.83379721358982,28.6484396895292));
#502=CARTESIAN_POINT('',(34.0656204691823,4.87800530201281,28.0694731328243));
#503=CARTESIAN_POINT('',(34.1597255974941,4.89776156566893,27.7754139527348));
#504=CARTESIAN_POINT('',(34.3232748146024,4.93225390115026,27.180228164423));
#505=CARTESIAN_POINT('',(34.3927189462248,4.94698998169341,26.8791015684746));
#506=CARTESIAN_POINT('',(34.5063857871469,4.97117989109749,26.2723608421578));
#507=CARTESIAN_POINT('',(34.5506442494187,4.98064120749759,25.96675370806));
#508=CARTESIAN_POINT('',(34.6137870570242,4.99415603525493,25.3528106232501));
#509=CARTESIAN_POINT('',(34.6326714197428,4.99820955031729,25.0444746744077));
#510=CARTESIAN_POINT('',(34.644935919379,5.00084099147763,24.4272603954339));
#511=CARTESIAN_POINT('',(34.6383150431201,4.9994187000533,24.1183820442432));
#512=CARTESIAN_POINT('',(34.5996125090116,4.9911218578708,23.5022985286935));
#513=CARTESIAN_POINT('',(34.5675308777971,4.9842473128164,23.1950933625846));
#514=CARTESIAN_POINT('',(34.4781950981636,4.96517513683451,22.5850017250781));
#515=CARTESIAN_POINT('',(34.4209785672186,4.95298546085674,22.2821094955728));
#516=CARTESIAN_POINT('',(34.2817747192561,4.92348679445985,21.6823260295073));
#517=CARTESIAN_POINT('',(34.1997873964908,4.9061778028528,21.3854347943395));
#518=CARTESIAN_POINT('',(34.0116119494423,4.86672680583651,20.799780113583));
#519=CARTESIAN_POINT('',(33.9054257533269,4.84458518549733,20.5110160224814));
#520=CARTESIAN_POINT('',(33.6695763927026,4.79582854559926,19.9436331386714));
#521=CARTESIAN_POINT('',(33.5399133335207,4.76921354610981,19.6650143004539));
#522=CARTESIAN_POINT('',(33.2578321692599,4.71190410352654,19.1195687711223));
#523=CARTESIAN_POINT('',(33.1053878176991,4.68120495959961,18.8527561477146));
#524=CARTESIAN_POINT('',(32.7788934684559,4.61623623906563,18.3331441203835));
#525=CARTESIAN_POINT('',(32.6048429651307,4.5819665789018,18.0803450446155));
#526=CARTESIAN_POINT('',(32.2363296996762,4.51038975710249,17.5905487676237));
#527=CARTESIAN_POINT('',(32.0418667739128,4.47308257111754,17.3535516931));
#528=CARTESIAN_POINT('',(31.6338671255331,4.39599896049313,16.8970435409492));
#529=CARTESIAN_POINT('',(31.4203320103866,4.3562227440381,16.6775309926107));
#530=CARTESIAN_POINT('',(31.0011481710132,4.27945832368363,16.2816097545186));
#531=CARTESIAN_POINT('',(30.797399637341,4.2426729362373,16.103144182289));
#532=CARTESIAN_POINT('',(30.3772054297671,4.168043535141,15.7621159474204));
#533=CARTESIAN_POINT('',(30.1607608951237,4.13019961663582,15.5995518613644));
#534=CARTESIAN_POINT('',(29.7163820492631,4.0538745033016,15.2912603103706));
#535=CARTESIAN_POINT('',(29.4884504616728,4.01539346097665,15.1455288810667));
#536=CARTESIAN_POINT('',(29.0222683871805,3.93818298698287,14.871631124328));
#537=CARTESIAN_POINT('',(28.7840165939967,3.89945352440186,14.7434670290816));
#538=CARTESIAN_POINT('',(28.5412428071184,3.86080360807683,14.6244916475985));
#539=B_SPLINE_CURVE_WITH_KNOTS('',3,(#457,#458,#459,#460,#461,#462,#463,#464,#465,#466,#467,
#468,#469,#470,#471,#472,#473,#474,#475,#476,#477,#478,#479,#480,#481,#482,#483,#484,#485,#486,
#487,#488,#489,#490,#491,#492,#493,#494,#495,#496,#497,#498,#499,#500,#501,#502,#503,#504,#505,
#506,#507,#508,#509,#510,#511,#512,#513,#514,#515,#516,#517,#518,#519,#520,#521,#522,#523,#524,
#525,#526,#527,#528,#529,#530,#531,#532,#533,#534,#535,#536,#537,#538),.UNSPECIFIED.,.F.,.F.,(4,
2,2,2,2,2,2,2,2,2,2,2,2,2,2,2,2,2,2,2,2,2,2,2,2,2,2,2,2,2,2,2,2,2,2,2,2,2,2,2,4),(0.,
0.928513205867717,1.85701780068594,2.78509470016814,3.71315042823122,4.64183578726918,
5.57051695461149,6.49892327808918,7.42732129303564,8.3512718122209,9.275221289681,
10.1993303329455,11.1234392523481,12.0461850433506,12.9689295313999,13.8916198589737,
14.8143126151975,15.7397117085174,16.6651124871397,17.5905476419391,18.5159833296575,
19.4430516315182,20.3701212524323,21.2971619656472,22.2242010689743,23.1499208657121,
24.0756400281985,25.0013959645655,25.9271509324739,26.8515250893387,27.7758994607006,
28.7002002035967,29.6244967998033,30.5498666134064,31.4752580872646,32.400656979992,
33.3259779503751,34.145266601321,34.9644818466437,35.7835037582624,36.6026296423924),.UNSPECIFIED.);
#540=CARTESIAN_POINT('',(20.5453214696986,2.87092129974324,35.0026521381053));
#541=VERTEX_POINT('',#540);
#542=CARTESIAN_POINT('',(28.5416508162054,3.86086857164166,14.6246916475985));
#543=VERTEX_POINT('',#542);
#544=EDGE_CURVE('E407',#541,#543,#539,.T.);
#545=ORIENTED_EDGE('',*,*,#544,.F.);
#546=CARTESIAN_POINT('',(20.5453214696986,-2.87092129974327,35.0026521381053));
#547=VERTEX_POINT('',#546);
#548=EDGE_CURVE('E497',#541,#547,#363,.T.);
#549=ORIENTED_EDGE('',*,*,#548,.T.);
#550=CARTESIAN_POINT('',(17.2511916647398,-2.62599221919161,33.3242100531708));
#551=CARTESIAN_POINT('',(17.4993781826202,-2.64089075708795,33.5086851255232));
#552=CARTESIAN_POINT('',(17.7552628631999,-2.65706460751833,33.6826969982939));
#553=CARTESIAN_POINT('',(18.28053769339,-2.69210530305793,34.0086627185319));
#554=CARTESIAN_POINT('',(18.5499277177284,-2.71097212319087,34.1606167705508));
#555=CARTESIAN_POINT('',(19.1002002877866,-2.75153205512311,34.4412740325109));
#556=CARTESIAN_POINT('',(19.3810774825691,-2.77322386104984,34.5699879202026));
#557=CARTESIAN_POINT('',(19.952432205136,-2.81952002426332,34.8033129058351));
#558=CARTESIAN_POINT('',(20.2429095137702,-2.84412431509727,34.9079245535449));
#559=CARTESIAN_POINT('',(20.8315983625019,-2.89628797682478,35.0923323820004));
#560=CARTESIAN_POINT('',(21.1298150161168,-2.92384934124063,35.1721116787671));
#561=CARTESIAN_POINT('',(21.7316508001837,-2.98187199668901,35.3061577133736));
#562=CARTESIAN_POINT('',(22.035269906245,-3.01233327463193,35.3604245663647));
#563=CARTESIAN_POINT('',(22.6456357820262,-3.07603596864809,35.4430189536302));
#564=CARTESIAN_POINT('',(22.9523815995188,-3.10927655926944,35.4713541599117));
#565=CARTESIAN_POINT('',(23.566877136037,-3.17836345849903,35.501889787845));
#566=CARTESIAN_POINT('',(23.874626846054,-3.21420974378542,35.504090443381));
#567=CARTESIAN_POINT('',(24.4874432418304,-3.2880770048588,35.4823817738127));
#568=CARTESIAN_POINT('',(24.7925157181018,-3.32608674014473,35.4585974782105));
#569=CARTESIAN_POINT('',(25.3992908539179,-3.40411737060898,35.3852808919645));
#570=CARTESIAN_POINT('',(25.7009935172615,-3.44413826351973,35.3357486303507));
#571=CARTESIAN_POINT('',(26.2989412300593,-3.52581537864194,35.211278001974));
#572=CARTESIAN_POINT('',(26.595185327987,-3.56747188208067,35.1363352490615));
#573=CARTESIAN_POINT('',(27.1800717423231,-3.65197221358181,34.9615826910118));
#574=CARTESIAN_POINT('',(27.4687140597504,-3.69481604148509,34.8617728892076));
#575=CARTESIAN_POINT('',(28.035952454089,-3.78113479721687,34.6381665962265));
#576=CARTESIAN_POINT('',(28.3145627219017,-3.82460870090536,34.514405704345));
#577=CARTESIAN_POINT('',(28.8602471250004,-3.91171735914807,34.2436848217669));
#578=CARTESIAN_POINT('',(29.1273212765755,-3.95535211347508,34.0967248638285));
#579=CARTESIAN_POINT('',(29.6480727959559,-4.04221651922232,33.7806574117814));
#580=CARTESIAN_POINT('',(29.9017509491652,-4.08544619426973,33.6115512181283));
#581=CARTESIAN_POINT('',(30.3939845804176,-4.17091924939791,33.2523788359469));
#582=CARTESIAN_POINT('',(30.6325400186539,-4.21316262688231,33.0623125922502));
#583=CARTESIAN_POINT('',(31.0935716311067,-4.29619199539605,32.6619711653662));
#584=CARTESIAN_POINT('',(31.3159985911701,-4.33697334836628,32.4516383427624));
#585=CARTESIAN_POINT('',(31.7424740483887,-4.41635307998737,32.0127202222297));
#586=CARTESIAN_POINT('',(31.9465225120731,-4.45495145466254,31.7841348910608));
#587=CARTESIAN_POINT('',(32.3348520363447,-4.52938773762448,31.3103146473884));
#588=CARTESIAN_POINT('',(32.5191323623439,-4.56522554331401,31.0650791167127));
#589=CARTESIAN_POINT('',(32.8666572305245,-4.63358841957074,30.5596945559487));
#590=CARTESIAN_POINT('',(33.0299017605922,-4.66611348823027,30.2995455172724));
#591=CARTESIAN_POINT('',(33.3345075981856,-4.72739462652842,29.7656976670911));
#592=CARTESIAN_POINT('',(33.4758297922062,-4.75614394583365,29.4919757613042));
#593=CARTESIAN_POINT('',(33.7352733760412,-4.80934524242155,28.9333467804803));
#594=CARTESIAN_POINT('',(33.8533947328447,-4.83379721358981,28.6484396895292));
#595=CARTESIAN_POINT('',(34.0656204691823,-4.87800530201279,28.0694731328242));
#596=CARTESIAN_POINT('',(34.1597255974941,-4.89776156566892,27.7754139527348));
#597=CARTESIAN_POINT('',(34.3232748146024,-4.93225390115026,27.180228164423));
#598=CARTESIAN_POINT('',(34.3927189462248,-4.94698998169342,26.8791015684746));
#599=CARTESIAN_POINT('',(34.5063857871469,-4.9711798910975,26.2723608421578));
#600=CARTESIAN_POINT('',(34.5506442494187,-4.98064120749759,25.96675370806));
#601=CARTESIAN_POINT('',(34.6137870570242,-4.99415603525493,25.3528106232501));
#602=CARTESIAN_POINT('',(34.6326714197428,-4.99820955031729,25.0444746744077));
#603=CARTESIAN_POINT('',(34.644935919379,-5.00084099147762,24.4272603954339));
#604=CARTESIAN_POINT('',(34.6383150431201,-4.99941870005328,24.1183820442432));
#605=CARTESIAN_POINT('',(34.5996125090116,-4.99112185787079,23.5022985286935));
#606=CARTESIAN_POINT('',(34.5675308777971,-4.98424731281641,23.1950933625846));
#607=CARTESIAN_POINT('',(34.4781950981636,-4.96517513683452,22.5850017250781));
#608=CARTESIAN_POINT('',(34.4209785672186,-4.95298546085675,22.2821094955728));
#609=CARTESIAN_POINT('',(34.2817747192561,-4.92348679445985,21.6823260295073));
#610=CARTESIAN_POINT('',(34.1997873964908,-4.9061778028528,21.3854347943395));
#611=CARTESIAN_POINT('',(34.0116119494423,-4.8667268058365,20.799780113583));
#612=CARTESIAN_POINT('',(33.9054257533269,-4.84458518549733,20.5110160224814));
#613=CARTESIAN_POINT('',(33.6695763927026,-4.79582854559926,19.9436331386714));
#614=CARTESIAN_POINT('',(33.5399133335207,-4.76921354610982,19.6650143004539));
#615=CARTESIAN_POINT('',(33.2578321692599,-4.71190410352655,19.1195687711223));
#616=CARTESIAN_POINT('',(33.1053878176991,-4.68120495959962,18.8527561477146));
#617=CARTESIAN_POINT('',(32.7788934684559,-4.61623623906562,18.3331441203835));
#618=CARTESIAN_POINT('',(32.6048429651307,-4.58196657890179,18.0803450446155));
#619=CARTESIAN_POINT('',(32.2363296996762,-4.51038975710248,17.5905487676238));
#620=CARTESIAN_POINT('',(32.0418667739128,-4.47308257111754,17.3535516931));
#621=CARTESIAN_POINT('',(31.6338671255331,-4.39599896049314,16.8970435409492));
#622=CARTESIAN_POINT('',(31.4203320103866,-4.35622274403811,16.6775309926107));
#623=CARTESIAN_POINT('',(31.0011481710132,-4.27945832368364,16.2816097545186));
#624=CARTESIAN_POINT('',(30.797399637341,-4.2426729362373,16.103144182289));
#625=CARTESIAN_POINT('',(30.3772054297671,-4.16804353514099,15.7621159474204));
#626=CARTESIAN_POINT('',(30.1607608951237,-4.13019961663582,15.5995518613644));
#627=CARTESIAN_POINT('',(29.7163820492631,-4.0538745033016,15.2912603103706));
#628=CARTESIAN_POINT('',(29.4884504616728,-4.01539346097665,15.1455288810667));
#629=CARTESIAN_POINT('',(29.0222683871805,-3.93818298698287,14.871631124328));
#630=CARTESIAN_POINT('',(28.7840165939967,-3.89945352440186,14.7434670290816));
#631=CARTESIAN_POINT('',(28.5412428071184,-3.86080360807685,14.6244916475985));
#632=B_SPLINE_CURVE_WITH_KNOTS('',3,(#550,#551,#552,#553,#554,#555,#556,#557,#558,#559,#560,
#561,#562,#563,#564,#565,#566,#567,#568,#569,#570,#571,#572,#573,#574,#575,#576,#577,#578,#579,
#580,#581,#582,#583,#584,#585,#586,#587,#588,#589,#590,#591,#592,#593,#594,#595,#596,#597,#598,
#599,#600,#601,#602,#603,#604,#605,#606,#607,#608,#609,#610,#611,#612,#613,#614,#615,#616,#617,
#618,#619,#620,#621,#622,#623,#624,#625,#626,#627,#628,#629,#630,#631),.UNSPECIFIED.,.F.,.F.,(4,
2,2,2,2,2,2,2,2,2,2,2,2,2,2,2,2,2,2,2,2,2,2,2,2,2,2,2,2,2,2,2,2,2,2,2,2,2,2,2,4),(0.,
0.928513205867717,1.85701780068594,2.78509470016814,3.71315042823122,4.64183578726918,
5.5705169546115,6.49892327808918,7.42732129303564,8.35127181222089,9.27522128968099,
10.1993303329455,11.1234392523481,12.0461850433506,12.9689295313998,13.8916198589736,
14.8143126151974,15.7397117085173,16.6651124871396,17.5905476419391,18.5159833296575,
19.4430516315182,20.3701212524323,21.2971619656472,22.2242010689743,23.1499208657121,
24.0756400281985,25.0013959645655,25.9271509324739,26.8515250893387,27.7758994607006,
28.7002002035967,29.6244967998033,30.5498666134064,31.4752580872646,32.400656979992,
33.3259779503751,34.145266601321,34.9644818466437,35.7835037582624,36.6026296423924),.UNSPECIFIED.);
#633=CARTESIAN_POINT('',(28.5416508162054,-3.86086857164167,14.6246916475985));
#634=VERTEX_POINT('',#633);
#635=EDGE_CURVE('E424',#547,#634,#632,.T.);
#636=ORIENTED_EDGE('',*,*,#635,.T.);
#637=EDGE_CURVE('E499',#543,#634,#201,.T.);
#638=ORIENTED_EDGE('',*,*,#637,.F.);
#639=EDGE_LOOP('',(#545,#549,#636,#638));
#640=FACE_BOUND('',#639,.T.);
#641=ADVANCED_FACE('F546',(#640),#271,.T.);
#642=CARTESIAN_POINT('',(0.,0.,108.668574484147));
#643=DIRECTION('',(0.,0.,-1.));
#644=DIRECTION('',(0.,1.,0.));
#645=AXIS2_PLACEMENT_3D('',#642,#643,#644);
#646=DEGENERATE_TOROIDAL_SURFACE('',#645,0.685062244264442,76.7197040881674,.F.);
#647=CARTESIAN_POINT('',(-20.5460071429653,2.87098210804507,35.0028521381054));
#648=CARTESIAN_POINT('',(-20.2734157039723,2.84680660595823,34.9233400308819));
#649=CARTESIAN_POINT('',(-20.000293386,2.82355619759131,34.8453661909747));
#650=CARTESIAN_POINT('',(-19.4530806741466,2.77893133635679,34.6925219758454));
#651=CARTESIAN_POINT('',(-19.1789904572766,2.75755655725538,34.6176510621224));
#652=CARTESIAN_POINT('',(-18.6298405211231,2.716700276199,34.4710118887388));
#653=CARTESIAN_POINT('',(-18.3547808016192,2.69721877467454,34.3992436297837));
#654=CARTESIAN_POINT('',(-17.8036907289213,2.66016623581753,34.2588105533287));
#655=CARTESIAN_POINT('',(-17.5276602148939,2.64259553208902,34.1901462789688));
#656=CARTESIAN_POINT('',(-17.2511916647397,2.6259922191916,34.1230468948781));
#657=B_SPLINE_CURVE_WITH_KNOTS('',3,(#647,#648,#649,#650,#651,#652,#653,#654,#655,#656),
.UNSPECIFIED.,.F.,.F.,(4,2,2,2,4),(0.,0.854929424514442,1.70970985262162,2.56449047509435,
3.41942009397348),.UNSPECIFIED.);
#658=CARTESIAN_POINT('',(-17.2513916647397,2.62600423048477,34.1230954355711));
#659=VERTEX_POINT('',#658);
#660=EDGE_CURVE('E154',#365,#659,#657,.T.);
#661=ORIENTED_EDGE('',*,*,#660,.F.);
#662=ORIENTED_EDGE('',*,*,#366,.F.);
#663=CARTESIAN_POINT('',(-20.5460071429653,-2.87098210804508,35.0028521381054));
#664=CARTESIAN_POINT('',(-20.2734157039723,-2.84680660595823,34.9233400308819));
#665=CARTESIAN_POINT('',(-20.000293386,-2.82355619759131,34.8453661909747));
#666=CARTESIAN_POINT('',(-19.4530806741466,-2.77893133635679,34.6925219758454));
#667=CARTESIAN_POINT('',(-19.1789904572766,-2.75755655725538,34.6176510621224));
#668=CARTESIAN_POINT('',(-18.6298405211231,-2.716700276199,34.4710118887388));
#669=CARTESIAN_POINT('',(-18.3547808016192,-2.69721877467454,34.3992436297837));
#670=CARTESIAN_POINT('',(-17.8036907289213,-2.66016623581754,34.2588105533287));
#671=CARTESIAN_POINT('',(-17.5276602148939,-2.64259553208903,34.1901462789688));
#672=CARTESIAN_POINT('',(-17.2511916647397,-2.62599221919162,34.1230468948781));
#673=B_SPLINE_CURVE_WITH_KNOTS('',3,(#663,#664,#665,#666,#667,#668,#669,#670,#671,#672),
.UNSPECIFIED.,.F.,.F.,(4,2,2,2,4),(0.,0.854929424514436,1.70970985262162,2.56449047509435,
3.41942009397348),.UNSPECIFIED.);
#674=CARTESIAN_POINT('',(-17.2513916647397,-2.62600423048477,34.1230954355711));
#675=VERTEX_POINT('',#674);
#676=EDGE_CURVE('E265',#356,#675,#673,.T.);
#677=ORIENTED_EDGE('',*,*,#676,.T.);
#678=CARTESIAN_POINT('',(-7.87158558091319,-6.16745020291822,32.6965849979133));
#679=CARTESIAN_POINT('',(-8.10636497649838,-5.93419521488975,32.7023351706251));
#680=CARTESIAN_POINT('',(-8.35057896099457,-5.71056381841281,32.7122920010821));
#681=CARTESIAN_POINT('',(-8.85594229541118,-5.28397951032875,32.7404382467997));
#682=CARTESIAN_POINT('',(-9.11708913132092,-5.0810235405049,32.7586264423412));
#683=CARTESIAN_POINT('',(-9.65391752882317,-4.69753542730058,32.803012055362));
#684=CARTESIAN_POINT('',(-9.92956896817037,-4.51695923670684,32.8291933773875));
#685=CARTESIAN_POINT('',(-10.4938637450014,-4.17888352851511,32.8893107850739));
#686=CARTESIAN_POINT('',(-10.7825070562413,-4.02138396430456,32.9232468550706));
#687=CARTESIAN_POINT('',(-11.3719049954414,-3.72979142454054,32.9987145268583));
#688=CARTESIAN_POINT('',(-11.6727041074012,-3.5957962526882,33.0402764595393));
#689=CARTESIAN_POINT('',(-12.283162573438,-3.35270795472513,33.1305442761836));
#690=CARTESIAN_POINT('',(-12.5928221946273,-3.24361558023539,33.1792503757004));
#691=CARTESIAN_POINT('',(-13.2188082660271,-3.05084636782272,33.283410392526));
#692=CARTESIAN_POINT('',(-13.5351339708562,-2.96716670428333,33.3388635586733));
#693=CARTESIAN_POINT('',(-14.1722163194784,-2.82551649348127,33.4560796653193));
#694=CARTESIAN_POINT('',(-14.4929719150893,-2.76753996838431,33.5178411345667));
#695=CARTESIAN_POINT('',(-15.2203602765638,-2.6657001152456,33.6640284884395));
#696=CARTESIAN_POINT('',(-15.6277375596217,-2.62937080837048,33.7501836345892));
#697=CARTESIAN_POINT('',(-16.2380432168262,-2.60540215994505,33.8856061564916));
#698=CARTESIAN_POINT('',(-16.4411994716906,-2.60249092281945,33.9317416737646));
#699=CARTESIAN_POINT('',(-16.8469304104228,-2.6067292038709,34.0259868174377));
#700=CARTESIAN_POINT('',(-17.0495051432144,-2.61387784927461,34.0740962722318));
#701=CARTESIAN_POINT('',(-17.2515916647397,-2.62601624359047,34.1231439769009));
#702=B_SPLINE_CURVE_WITH_KNOTS('',3,(#678,#679,#680,#681,#682,#683,#684,#685,#686,#687,#688,
#689,#690,#691,#692,#693,#694,#695,#696,#697,#698,#699,#700,#701),.UNSPECIFIED.,.F.,.F.,(4,2,2,
2,2,2,2,2,2,2,2,4),(0.,0.992684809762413,1.98522257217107,2.97577473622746,3.96632489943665,
4.96090379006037,5.95551269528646,6.95001097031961,7.94427783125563,9.1958250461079,
9.82066105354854,10.4454428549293),.UNSPECIFIED.);
#703=CARTESIAN_POINT('',(-7.8717855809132,-6.16725155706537,32.6965899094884));
#704=VERTEX_POINT('',#703);
#705=EDGE_CURVE('E458',#704,#675,#702,.T.);
#706=ORIENTED_EDGE('',*,*,#705,.F.);
#707=CARTESIAN_POINT('',(0.,0.,32.6965899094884));
#708=DIRECTION('',(0.,0.,1.));
#709=DIRECTION('',(0.,-1.,0.));
#710=AXIS2_PLACEMENT_3D('',#707,#708,#709);
#711=CIRCLE('',#710,10.);
#712=CARTESIAN_POINT('',(7.8717855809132,-6.16725155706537,32.6965899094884));
#713=VERTEX_POINT('',#712);
#714=EDGE_CURVE('E455',#713,#704,#711,.F.);
#715=ORIENTED_EDGE('',*,*,#714,.F.);
#716=CARTESIAN_POINT('',(7.87158558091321,-6.16745020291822,32.6965849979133));
#717=CARTESIAN_POINT('',(8.10636497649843,-5.93419521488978,32.7023351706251));
#718=CARTESIAN_POINT('',(8.35057896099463,-5.71056381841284,32.7122920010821));
#719=CARTESIAN_POINT('',(8.85594229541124,-5.28397951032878,32.7404382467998));
#720=CARTESIAN_POINT('',(9.11708913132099,-5.08102354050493,32.7586264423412));
#721=CARTESIAN_POINT('',(9.65391752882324,-4.69753542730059,32.803012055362));
#722=CARTESIAN_POINT('',(9.92956896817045,-4.51695923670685,32.8291933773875));
#723=CARTESIAN_POINT('',(10.4938637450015,-4.17888352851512,32.8893107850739));
#724=CARTESIAN_POINT('',(10.7825070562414,-4.02138396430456,32.9232468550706));
#725=CARTESIAN_POINT('',(11.3719049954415,-3.72979142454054,32.9987145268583));
#726=CARTESIAN_POINT('',(11.6727041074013,-3.5957962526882,33.0402764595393));
#727=CARTESIAN_POINT('',(12.2831625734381,-3.35270795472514,33.1305442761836));
#728=CARTESIAN_POINT('',(12.5928221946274,-3.2436155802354,33.1792503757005));
#729=CARTESIAN_POINT('',(13.2188082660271,-3.05084636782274,33.283410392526));
#730=CARTESIAN_POINT('',(13.5351339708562,-2.96716670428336,33.3388635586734));
#731=CARTESIAN_POINT('',(14.1722163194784,-2.82551649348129,33.4560796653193));
#732=CARTESIAN_POINT('',(14.4929719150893,-2.76753996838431,33.5178411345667));
#733=CARTESIAN_POINT('',(15.2203602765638,-2.6657001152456,33.6640284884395));
#734=CARTESIAN_POINT('',(15.6277375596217,-2.62937080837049,33.7501836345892));
#735=CARTESIAN_POINT('',(16.2380432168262,-2.60540215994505,33.8856061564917));
#736=CARTESIAN_POINT('',(16.4411994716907,-2.60249092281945,33.9317416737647));
#737=CARTESIAN_POINT('',(16.8469304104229,-2.6067292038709,34.0259868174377));
#738=CARTESIAN_POINT('',(17.0495051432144,-2.61387784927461,34.0740962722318));
#739=CARTESIAN_POINT('',(17.2515916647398,-2.62601624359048,34.1231439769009));
#740=B_SPLINE_CURVE_WITH_KNOTS('',3,(#716,#717,#718,#719,#720,#721,#722,#723,#724,#725,#726,
#727,#728,#729,#730,#731,#732,#733,#734,#735,#736,#737,#738,#739),.UNSPECIFIED.,.F.,.F.,(4,2,2,
2,2,2,2,2,2,2,2,4),(0.,0.992684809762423,1.98522257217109,2.9757747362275,3.9663248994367,
4.96090379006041,5.95551269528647,6.95001097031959,7.94427783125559,9.1958250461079,
9.82066105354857,10.4454428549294),.UNSPECIFIED.);
#741=CARTESIAN_POINT('',(17.2513916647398,-2.62600423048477,34.1230954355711));
#742=VERTEX_POINT('',#741);
#743=EDGE_CURVE('E204',#713,#742,#740,.T.);
#744=ORIENTED_EDGE('',*,*,#743,.T.);
#745=CARTESIAN_POINT('',(20.5460071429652,-2.87098210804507,35.0028521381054));
#746=CARTESIAN_POINT('',(20.2734157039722,-2.84680660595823,34.9233400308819));
#747=CARTESIAN_POINT('',(20.0002933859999,-2.82355619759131,34.8453661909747));
#748=CARTESIAN_POINT('',(19.4530806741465,-2.77893133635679,34.6925219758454));
#749=CARTESIAN_POINT('',(19.1789904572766,-2.75755655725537,34.6176510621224));
#750=CARTESIAN_POINT('',(18.6298405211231,-2.71670027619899,34.4710118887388));
#751=CARTESIAN_POINT('',(18.3547808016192,-2.69721877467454,34.3992436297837));
#752=CARTESIAN_POINT('',(17.8036907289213,-2.66016623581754,34.2588105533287));
#753=CARTESIAN_POINT('',(17.527660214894,-2.64259553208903,34.1901462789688));
#754=CARTESIAN_POINT('',(17.2511916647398,-2.62599221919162,34.1230468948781));
#755=B_SPLINE_CURVE_WITH_KNOTS('',3,(#745,#746,#747,#748,#749,#750,#751,#752,#753,#754),
.UNSPECIFIED.,.F.,.F.,(4,2,2,2,4),(0.,0.854929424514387,1.70970985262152,2.5644904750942,
3.41942009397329),.UNSPECIFIED.);
#756=EDGE_CURVE('E452',#547,#742,#755,.T.);
#757=ORIENTED_EDGE('',*,*,#756,.F.);
#758=ORIENTED_EDGE('',*,*,#548,.F.);
#759=CARTESIAN_POINT('',(20.5460071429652,2.87098210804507,35.0028521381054));
#760=CARTESIAN_POINT('',(20.2734157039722,2.84680660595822,34.9233400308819));
#761=CARTESIAN_POINT('',(20.0002933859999,2.8235561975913,34.8453661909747));
#762=CARTESIAN_POINT('',(19.4530806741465,2.77893133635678,34.6925219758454));
#763=CARTESIAN_POINT('',(19.1789904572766,2.75755655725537,34.6176510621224));
#764=CARTESIAN_POINT('',(18.6298405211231,2.71670027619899,34.4710118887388));
#765=CARTESIAN_POINT('',(18.3547808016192,2.69721877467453,34.3992436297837));
#766=CARTESIAN_POINT('',(17.8036907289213,2.66016623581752,34.2588105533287));
#767=CARTESIAN_POINT('',(17.527660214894,2.64259553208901,34.1901462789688));
#768=CARTESIAN_POINT('',(17.2511916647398,2.6259922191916,34.1230468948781));
#769=B_SPLINE_CURVE_WITH_KNOTS('',3,(#759,#760,#761,#762,#763,#764,#765,#766,#767,#768),
.UNSPECIFIED.,.F.,.F.,(4,2,2,2,4),(0.,0.854929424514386,1.70970985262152,2.5644904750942,
3.41942009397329),.UNSPECIFIED.);
#770=CARTESIAN_POINT('',(17.2513916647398,2.62600423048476,34.1230954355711));
#771=VERTEX_POINT('',#770);
#772=EDGE_CURVE('E261',#541,#771,#769,.T.);
#773=ORIENTED_EDGE('',*,*,#772,.T.);
#774=CARTESIAN_POINT('',(7.87158558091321,6.16745020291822,32.6965849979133));
#775=CARTESIAN_POINT('',(8.10636497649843,5.93419521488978,32.7023351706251));
#776=CARTESIAN_POINT('',(8.35057896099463,5.71056381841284,32.7122920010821));
#777=CARTESIAN_POINT('',(8.85594229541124,5.28397951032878,32.7404382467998));
#778=CARTESIAN_POINT('',(9.11708913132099,5.08102354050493,32.7586264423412));
#779=CARTESIAN_POINT('',(9.65391752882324,4.69753542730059,32.803012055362));
#780=CARTESIAN_POINT('',(9.92956896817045,4.51695923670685,32.8291933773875));
#781=CARTESIAN_POINT('',(10.4938637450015,4.17888352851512,32.8893107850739));
#782=CARTESIAN_POINT('',(10.7825070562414,4.02138396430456,32.9232468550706));
#783=CARTESIAN_POINT('',(11.3719049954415,3.72979142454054,32.9987145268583));
#784=CARTESIAN_POINT('',(11.6727041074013,3.5957962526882,33.0402764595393));
#785=CARTESIAN_POINT('',(12.2831625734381,3.35270795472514,33.1305442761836));
#786=CARTESIAN_POINT('',(12.5928221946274,3.2436155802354,33.1792503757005));
#787=CARTESIAN_POINT('',(13.2188082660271,3.05084636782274,33.283410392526));
#788=CARTESIAN_POINT('',(13.5351339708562,2.96716670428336,33.3388635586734));
#789=CARTESIAN_POINT('',(14.1722163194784,2.82551649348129,33.4560796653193));
#790=CARTESIAN_POINT('',(14.4929719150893,2.76753996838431,33.5178411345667));
#791=CARTESIAN_POINT('',(15.2203602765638,2.6657001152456,33.6640284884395));
#792=CARTESIAN_POINT('',(15.6277375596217,2.62937080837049,33.7501836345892));
#793=CARTESIAN_POINT('',(16.2380432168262,2.60540215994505,33.8856061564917));
#794=CARTESIAN_POINT('',(16.4411994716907,2.60249092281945,33.9317416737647));
#795=CARTESIAN_POINT('',(16.8469304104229,2.6067292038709,34.0259868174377));
#796=CARTESIAN_POINT('',(17.0495051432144,2.61387784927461,34.0740962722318));
#797=CARTESIAN_POINT('',(17.2515916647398,2.62601624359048,34.1231439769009));
#798=B_SPLINE_CURVE_WITH_KNOTS('',3,(#774,#775,#776,#777,#778,#779,#780,#781,#782,#783,#784,
#785,#786,#787,#788,#789,#790,#791,#792,#793,#794,#795,#796,#797),.UNSPECIFIED.,.F.,.F.,(4,2,2,
2,2,2,2,2,2,2,2,4),(0.,0.992684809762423,1.98522257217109,2.9757747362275,3.9663248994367,
4.96090379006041,5.95551269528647,6.95001097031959,7.94427783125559,9.1958250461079,
9.82066105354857,10.4454428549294),.UNSPECIFIED.);
#799=CARTESIAN_POINT('',(7.8717855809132,6.16725155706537,32.6965899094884));
#800=VERTEX_POINT('',#799);
#801=EDGE_CURVE('E247',#800,#771,#798,.T.);
#802=ORIENTED_EDGE('',*,*,#801,.F.);
#803=CARTESIAN_POINT('',(0.,0.,32.6965899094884));
#804=DIRECTION('',(0.,0.,1.));
#805=DIRECTION('',(0.,-1.,0.));
#806=AXIS2_PLACEMENT_3D('',#803,#804,#805);
#807=CIRCLE('',#806,10.);
#808=CARTESIAN_POINT('',(-7.8717855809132,6.16725155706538,32.6965899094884));
#809=VERTEX_POINT('',#808);
#810=EDGE_CURVE('E258',#809,#800,#807,.F.);
#811=ORIENTED_EDGE('',*,*,#810,.F.);
#812=CARTESIAN_POINT('',(-7.87158558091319,6.1674502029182,32.6965849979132));
#813=CARTESIAN_POINT('',(-8.10636497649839,5.93419521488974,32.702335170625));
#814=CARTESIAN_POINT('',(-8.35057896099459,5.71056381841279,32.7122920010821));
#815=CARTESIAN_POINT('',(-8.8559422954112,5.28397951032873,32.7404382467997));
#816=CARTESIAN_POINT('',(-9.11708913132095,5.08102354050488,32.7586264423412));
#817=CARTESIAN_POINT('',(-9.65391752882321,4.69753542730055,32.803012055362));
#818=CARTESIAN_POINT('',(-9.92956896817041,4.5169592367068,32.8291933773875));
#819=CARTESIAN_POINT('',(-10.4938637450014,4.17888352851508,32.8893107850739));
#820=CARTESIAN_POINT('',(-10.7825070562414,4.02138396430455,32.9232468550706));
#821=CARTESIAN_POINT('',(-11.3719049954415,3.72979142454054,32.9987145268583));
#822=CARTESIAN_POINT('',(-11.6727041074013,3.59579625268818,33.0402764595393));
#823=CARTESIAN_POINT('',(-12.2831625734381,3.3527079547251,33.1305442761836));
#824=CARTESIAN_POINT('',(-12.5928221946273,3.24361558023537,33.1792503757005));
#825=CARTESIAN_POINT('',(-13.2188082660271,3.05084636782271,33.283410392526));
#826=CARTESIAN_POINT('',(-13.5351339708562,2.96716670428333,33.3388635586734));
#827=CARTESIAN_POINT('',(-14.1722163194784,2.82551649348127,33.4560796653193));
#828=CARTESIAN_POINT('',(-14.4929719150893,2.76753996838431,33.5178411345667));
#829=CARTESIAN_POINT('',(-15.2203602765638,2.6657001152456,33.6640284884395));
#830=CARTESIAN_POINT('',(-15.6277375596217,2.62937080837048,33.7501836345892));
#831=CARTESIAN_POINT('',(-16.2380432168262,2.60540215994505,33.8856061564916));
#832=CARTESIAN_POINT('',(-16.4411994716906,2.60249092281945,33.9317416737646));
#833=CARTESIAN_POINT('',(-16.8469304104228,2.6067292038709,34.0259868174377));
#834=CARTESIAN_POINT('',(-17.0495051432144,2.61387784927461,34.0740962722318));
#835=CARTESIAN_POINT('',(-17.2515916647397,2.62601624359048,34.1231439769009));
#836=B_SPLINE_CURVE_WITH_KNOTS('',3,(#812,#813,#814,#815,#816,#817,#818,#819,#820,#821,#822,
#823,#824,#825,#826,#827,#828,#829,#830,#831,#832,#833,#834,#835),.UNSPECIFIED.,.F.,.F.,(4,2,2,
2,2,2,2,2,2,2,2,4),(0.,0.992684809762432,1.9852225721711,2.97577473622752,3.96632489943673,
4.96090379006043,5.9555126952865,6.95001097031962,7.94427783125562,9.19582504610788,
9.82066105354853,10.4454428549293),.UNSPECIFIED.);
#837=EDGE_CURVE('E263',#809,#659,#836,.T.);
#838=ORIENTED_EDGE('',*,*,#837,.T.);
#839=EDGE_LOOP('',(#661,#662,#677,#706,#715,#744,#757,#758,#773,#802,#811,#838));
#840=FACE_BOUND('',#839,.T.);
#841=CARTESIAN_POINT('',(0.,0.,32.373184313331));
#842=DIRECTION('',(0.,0.,-1.));
#843=DIRECTION('',(0.,1.,0.));
#844=AXIS2_PLACEMENT_3D('',#841,#842,#843);
#845=CIRCLE('',#844,7.37263184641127);
#846=CARTESIAN_POINT('',(0.,7.37263184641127,32.373184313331));
#847=VERTEX_POINT('',#846);
#848=EDGE_CURVE('E493',#847,#847,#845,.T.);
#849=ORIENTED_EDGE('',*,*,#848,.T.);
#850=EDGE_LOOP('',(#849));
#851=FACE_BOUND('',#850,.T.);
#852=ADVANCED_FACE('F256',(#840,#851),#646,.T.);
#853=CARTESIAN_POINT('',(0.,0.,26.6930075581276));
#854=DIRECTION('',(0.,-1.,0.));
#855=DIRECTION('',(1.,0.,0.));
#856=AXIS2_PLACEMENT_3D('',#853,#854,#855);
#857=SPHERICAL_SURFACE('',#856,9.30699244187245);
#858=CARTESIAN_POINT('',(0.,0.,26.6930075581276));
#859=DIRECTION('',(0.,0.,-1.));
#860=DIRECTION('',(0.,1.,0.));
#861=AXIS2_PLACEMENT_3D('',#858,#859,#860);
#862=SPHERICAL_SURFACE('',#861,9.30699244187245);
#863=ORIENTED_EDGE('',*,*,#848,.F.);
#864=EDGE_LOOP('',(#863));
#865=FACE_BOUND('',#864,.T.);
#866=ADVANCED_FACE('F16',(#865),#862,.T.);
#867=CARTESIAN_POINT('',(4.,0.,20.));
#868=DIRECTION('',(0.,0.,1.));
#869=DIRECTION('',(0.,-1.,0.));
#870=AXIS2_PLACEMENT_3D('',#867,#868,#869);
#871=PLANE('',#870);
#872=CARTESIAN_POINT('',(0.,0.,20.));
#873=DIRECTION('',(0.,0.,-1.));
#874=DIRECTION('',(0.,1.,0.));
#875=AXIS2_PLACEMENT_3D('',#872,#873,#874);
#876=CIRCLE('',#875,4.);
#877=CARTESIAN_POINT('',(0.,4.,20.));
#878=VERTEX_POINT('',#877);
#879=EDGE_CURVE('E447',#878,#878,#876,.T.);
#880=ORIENTED_EDGE('',*,*,#879,.T.);
#881=EDGE_LOOP('',(#880));
#882=FACE_BOUND('',#881,.T.);
#883=ADVANCED_FACE('F559',(#882),#871,.F.);
#884=CARTESIAN_POINT('',(0.,0.,-2.33088640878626));
#885=DIRECTION('',(0.,0.,-1.));
#886=DIRECTION('',(0.,1.,0.));
#887=AXIS2_PLACEMENT_3D('',#884,#885,#886);
#888=CYLINDRICAL_SURFACE('',#887,4.);
#889=CARTESIAN_POINT('',(0.,0.,0.));
#890=DIRECTION('',(0.,0.,-1.));
#891=DIRECTION('',(0.,1.,0.));
#892=AXIS2_PLACEMENT_3D('',#889,#890,#891);
#893=CIRCLE('',#892,4.);
#894=CARTESIAN_POINT('',(0.,4.,0.));
#895=VERTEX_POINT('',#894);
#896=EDGE_CURVE('E440',#895,#895,#893,.T.);
#897=ORIENTED_EDGE('',*,*,#896,.T.);
#898=EDGE_LOOP('',(#897));
#899=FACE_BOUND('',#898,.T.);
#900=ORIENTED_EDGE('',*,*,#879,.F.);
#901=EDGE_LOOP('',(#900));
#902=FACE_BOUND('',#901,.T.);
#903=ADVANCED_FACE('F565',(#899,#902),#888,.F.);
#904=CARTESIAN_POINT('',(10.,0.,0.));
#905=DIRECTION('',(0.,0.,1.));
#906=DIRECTION('',(0.,-1.,0.));
#907=AXIS2_PLACEMENT_3D('',#904,#905,#906);
#908=PLANE('',#907);
#909=ORIENTED_EDGE('',*,*,#896,.F.);
#910=EDGE_LOOP('',(#909));
#911=FACE_BOUND('',#910,.T.);
#912=CARTESIAN_POINT('',(0.,0.,0.));
#913=DIRECTION('',(0.,0.,-1.));
#914=DIRECTION('',(0.,1.,0.));
#915=AXIS2_PLACEMENT_3D('',#912,#913,#914);
#916=CIRCLE('',#915,10.);
#917=CARTESIAN_POINT('',(0.,10.,0.));
#918=VERTEX_POINT('',#917);
#919=EDGE_CURVE('E436',#918,#918,#916,.T.);
#920=ORIENTED_EDGE('',*,*,#919,.T.);
#921=EDGE_LOOP('',(#920));
#922=FACE_BOUND('',#921,.T.);
#923=ADVANCED_FACE('F571',(#911,#922),#908,.F.);
#924=CARTESIAN_POINT('',(0.,0.,-2.33088640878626));
#925=DIRECTION('',(0.,0.,-1.));
#926=DIRECTION('',(0.,1.,0.));
#927=AXIS2_PLACEMENT_3D('',#924,#925,#926);
#928=CYLINDRICAL_SURFACE('',#927,10.);
#929=ORIENTED_EDGE('',*,*,#919,.F.);
#930=EDGE_LOOP('',(#929));
#931=FACE_BOUND('',#930,.T.);
#932=DIRECTION('',(0.,0.,1.));
#933=VECTOR('',#932,1.);
#934=CARTESIAN_POINT('',(-7.8717855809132,-6.16725155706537,-6.26382242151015));
#935=LINE('',#934,#933);
#936=EDGE_CURVE('E167',#66,#704,#935,.T.);
#937=ORIENTED_EDGE('',*,*,#936,.F.);
#938=ORIENTED_EDGE('',*,*,#126,.T.);
#939=DIRECTION('',(0.,0.,1.));
#940=VECTOR('',#939,1.);
#941=CARTESIAN_POINT('',(-7.8717855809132,6.16725155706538,-6.26382242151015));
#942=LINE('',#941,#940);
#943=EDGE_CURVE('E156',#118,#809,#942,.T.);
#944=ORIENTED_EDGE('',*,*,#943,.T.);
#945=ORIENTED_EDGE('',*,*,#810,.T.);
#946=DIRECTION('',(0.,0.,1.));
#947=VECTOR('',#946,1.);
#948=CARTESIAN_POINT('',(7.8717855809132,6.16725155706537,-6.26382242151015));
#949=LINE('',#948,#947);
#950=CARTESIAN_POINT('',(7.8717855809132,6.16725155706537,8.));
#951=VERTEX_POINT('',#950);
#952=EDGE_CURVE('E160',#951,#800,#949,.T.);
#953=ORIENTED_EDGE('',*,*,#952,.F.);
#954=CARTESIAN_POINT('',(7.8717855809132,-6.16725155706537,8.));
#955=VERTEX_POINT('',#954);
#956=EDGE_CURVE('E433',#951,#955,#125,.T.);
#957=ORIENTED_EDGE('',*,*,#956,.T.);
#958=DIRECTION('',(0.,0.,1.));
#959=VECTOR('',#958,1.);
#960=CARTESIAN_POINT('',(7.8717855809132,-6.16725155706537,-6.26382242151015));
#961=LINE('',#960,#959);
#962=EDGE_CURVE('E222',#955,#713,#961,.T.);
#963=ORIENTED_EDGE('',*,*,#962,.T.);
#964=ORIENTED_EDGE('',*,*,#714,.T.);
#965=EDGE_LOOP('',(#937,#938,#944,#945,#953,#957,#963,#964));
#966=FACE_BOUND('',#965,.T.);
#967=ADVANCED_FACE('F311',(#931,#966),#928,.T.);
#968=CARTESIAN_POINT('',(10.936400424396,3.94636818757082,9.7916319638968));
#969=CARTESIAN_POINT('',(10.824118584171,4.003704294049,9.78325234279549));
#970=CARTESIAN_POINT('',(10.7132133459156,4.06254400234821,9.76897182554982));
#971=CARTESIAN_POINT('',(10.4947965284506,4.18269546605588,9.73031315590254));
#972=CARTESIAN_POINT('',(10.3872790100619,4.24400241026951,9.70595387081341));
#973=CARTESIAN_POINT('',(10.1765147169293,4.36838152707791,9.64897611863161));
#974=CARTESIAN_POINT('',(10.0732455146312,4.43144032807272,9.61641003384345));
#975=CARTESIAN_POINT('',(9.87034998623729,4.55941800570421,9.54423053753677));
#976=CARTESIAN_POINT('',(9.77072514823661,4.62433762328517,9.50461428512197));
#977=CARTESIAN_POINT('',(9.5507649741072,4.77218804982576,9.40879869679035));
#978=CARTESIAN_POINT('',(9.43146470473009,4.8555710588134,9.350928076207));
#979=CARTESIAN_POINT('',(9.1984542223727,5.02453572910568,9.22749490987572));
#980=CARTESIAN_POINT('',(9.08474708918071,5.11011856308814,9.1619281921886));
#981=CARTESIAN_POINT('',(8.89583509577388,5.25740071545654,9.04459290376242));
#982=CARTESIAN_POINT('',(8.81922141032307,5.31864764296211,8.99450670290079));
#983=CARTESIAN_POINT('',(8.66877804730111,5.44185241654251,8.89113944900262));
#984=CARTESIAN_POINT('',(8.59494804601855,5.50381017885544,8.83785876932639));
#985=CARTESIAN_POINT('',(8.47417990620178,5.60755853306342,8.74594898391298));
#986=CARTESIAN_POINT('',(8.42641392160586,5.64925103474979,8.70829311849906));
#987=CARTESIAN_POINT('',(8.33242521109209,5.73256077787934,8.63109723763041));
#988=CARTESIAN_POINT('',(8.28620142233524,5.77417805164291,8.59155856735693));
#989=CARTESIAN_POINT('',(8.21125367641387,5.8426693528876,8.52388347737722));
#990=CARTESIAN_POINT('',(8.18198002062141,5.86968993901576,8.49650386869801));
#991=CARTESIAN_POINT('',(8.12444979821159,5.92330159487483,8.44010631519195));
#992=CARTESIAN_POINT('',(8.09619524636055,5.94989176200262,8.41108538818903));
#993=CARTESIAN_POINT('',(8.0423403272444,6.00103726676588,8.35179046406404));
#994=CARTESIAN_POINT('',(8.01668026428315,6.02563150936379,8.3216036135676));
#995=CARTESIAN_POINT('',(7.96790958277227,6.07276025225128,8.25760239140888));
#996=CARTESIAN_POINT('',(7.94479257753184,6.09529988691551,8.22379754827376));
#997=CARTESIAN_POINT('',(7.9170132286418,6.12255630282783,8.17250880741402));
#998=CARTESIAN_POINT('',(7.90975258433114,6.12970126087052,8.15779331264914));
#999=CARTESIAN_POINT('',(7.8966543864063,6.14261741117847,8.1272758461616));
#1000=CARTESIAN_POINT('',(7.89080740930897,6.14839769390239,8.11148202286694));
#1001=CARTESIAN_POINT('',(7.88158226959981,6.15753000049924,8.08013275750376));
#1002=CARTESIAN_POINT('',(7.87802903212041,6.16105398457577,8.06468423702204));
#1003=CARTESIAN_POINT('',(7.8730756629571,6.16597001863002,8.03281428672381));
#1004=CARTESIAN_POINT('',(7.87172008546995,6.1673179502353,8.01637956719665));
#1005=CARTESIAN_POINT('',(7.87178564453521,6.16725149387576,7.9998));
#1006=B_SPLINE_CURVE_WITH_KNOTS('',3,(#968,#969,#970,#971,#972,#973,#974,#975,#976,#977,#978,
#979,#980,#981,#982,#983,#984,#985,#986,#987,#988,#989,#990,#991,#992,#993,#994,#995,#996,#997,
#998,#999,#1000,#1001,#1002,#1003,#1004,#1005),.UNSPECIFIED.,.F.,.F.,(4,2,2,2,2,2,2,2,2,2,2,2,2,
2,2,2,2,2,4),(0.,0.378686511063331,0.756667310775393,1.13229407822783,1.50807255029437,
1.97761636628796,2.44741590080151,2.77774393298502,3.10803343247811,3.32923096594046,
3.55027276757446,3.69527147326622,3.84054267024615,3.98039395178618,4.11988557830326,
4.17347981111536,4.22670627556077,4.27513325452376,4.32453026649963),.UNSPECIFIED.);
#1007=CARTESIAN_POINT('',(10.9337221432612,3.94773654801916,9.7914319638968));
#1008=VERTEX_POINT('',#1007);
#1009=EDGE_CURVE('E250',#1008,#951,#1006,.T.);
#1010=ORIENTED_EDGE('',*,*,#1009,.F.);
#1011=CARTESIAN_POINT('',(10.9337221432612,-3.94773654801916,9.7914319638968));
#1012=VERTEX_POINT('',#1011);
#1013=EDGE_CURVE('E406',#1008,#1012,#73,.T.);
#1014=ORIENTED_EDGE('',*,*,#1013,.T.);
#1015=CARTESIAN_POINT('',(10.9364004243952,-3.94636818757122,9.79163196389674));
#1016=CARTESIAN_POINT('',(10.8241185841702,-4.00370429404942,9.7832523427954));
#1017=CARTESIAN_POINT('',(10.7132133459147,-4.06254400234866,9.7689718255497));
#1018=CARTESIAN_POINT('',(10.4947965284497,-4.18269546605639,9.73031315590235));
#1019=CARTESIAN_POINT('',(10.387279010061,-4.24400241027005,9.70595387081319));
#1020=CARTESIAN_POINT('',(10.1765147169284,-4.36838152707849,9.64897611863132));
#1021=CARTESIAN_POINT('',(10.0732455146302,-4.43144032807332,9.61641003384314));
#1022=CARTESIAN_POINT('',(9.8703499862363,-4.55941800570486,9.54423053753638));
#1023=CARTESIAN_POINT('',(9.77072514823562,-4.62433762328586,9.50461428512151));
#1024=CARTESIAN_POINT('',(9.55076497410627,-4.77218804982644,9.40879869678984));
#1025=CARTESIAN_POINT('',(9.43146470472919,-4.85557105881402,9.35092807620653));
#1026=CARTESIAN_POINT('',(9.19845422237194,-5.02453572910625,9.2274949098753));
#1027=CARTESIAN_POINT('',(9.08474708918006,-5.11011856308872,9.16192819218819));
#1028=CARTESIAN_POINT('',(8.89583509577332,-5.25740071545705,9.04459290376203));
#1029=CARTESIAN_POINT('',(8.81922141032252,-5.31864764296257,8.99450670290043));
#1030=CARTESIAN_POINT('',(8.66877804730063,-5.4418524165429,8.89113944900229));
#1031=CARTESIAN_POINT('',(8.59494804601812,-5.50381017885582,8.83785876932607));
#1032=CARTESIAN_POINT('',(8.47417990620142,-5.60755853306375,8.7459489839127));
#1033=CARTESIAN_POINT('',(8.42641392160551,-5.64925103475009,8.7082931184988));
#1034=CARTESIAN_POINT('',(8.33242521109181,-5.7325607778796,8.63109723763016));
#1035=CARTESIAN_POINT('',(8.28620142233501,-5.77417805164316,8.59155856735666));
#1036=CARTESIAN_POINT('',(8.21125367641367,-5.84266935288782,8.52388347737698));
#1037=CARTESIAN_POINT('',(8.18198002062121,-5.86968993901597,8.49650386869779));
#1038=CARTESIAN_POINT('',(8.12444979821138,-5.92330159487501,8.44010631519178));
#1039=CARTESIAN_POINT('',(8.09619524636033,-5.94989176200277,8.41108538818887));
#1040=CARTESIAN_POINT('',(8.0423403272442,-6.00103726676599,8.3517904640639));
#1041=CARTESIAN_POINT('',(8.016680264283,-6.02563150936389,8.32160361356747));
#1042=CARTESIAN_POINT('',(7.96790958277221,-6.07276025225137,8.25760239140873));
#1043=CARTESIAN_POINT('',(7.94479257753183,-6.09529988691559,8.22379754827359));
#1044=CARTESIAN_POINT('',(7.9170132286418,-6.12255630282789,8.17250880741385));
#1045=CARTESIAN_POINT('',(7.90975258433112,-6.12970126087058,8.15779331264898));
#1046=CARTESIAN_POINT('',(7.89665438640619,-6.14261741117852,8.12727584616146));
#1047=CARTESIAN_POINT('',(7.89080740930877,-6.14839769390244,8.11148202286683));
#1048=CARTESIAN_POINT('',(7.88158226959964,-6.15753000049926,8.08013275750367));
#1049=CARTESIAN_POINT('',(7.87802903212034,-6.16105398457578,8.06468423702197));
#1050=CARTESIAN_POINT('',(7.87307566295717,-6.16597001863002,8.03281428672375));
#1051=CARTESIAN_POINT('',(7.87172008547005,-6.16731795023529,8.0163795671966));
#1052=CARTESIAN_POINT('',(7.87178564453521,-6.16725149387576,7.9998));
#1053=B_SPLINE_CURVE_WITH_KNOTS('',3,(#1015,#1016,#1017,#1018,#1019,#1020,#1021,#1022,#1023,
#1024,#1025,#1026,#1027,#1028,#1029,#1030,#1031,#1032,#1033,#1034,#1035,#1036,#1037,#1038,#1039,
#1040,#1041,#1042,#1043,#1044,#1045,#1046,#1047,#1048,#1049,#1050,#1051,#1052),.UNSPECIFIED.,
.F.,.F.,(4,2,2,2,2,2,2,2,2,2,2,2,2,2,2,2,2,2,4),(0.,0.378686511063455,0.756667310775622,
1.13229407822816,1.5080725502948,1.97761636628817,2.44741590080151,2.77774393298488,
3.10803343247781,3.32923096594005,3.55027276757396,3.69527147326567,3.84054267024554,
3.98039395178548,4.11988557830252,4.17347981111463,4.22670627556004,4.27513325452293,
4.32453026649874),.UNSPECIFIED.);
#1054=EDGE_CURVE('E178',#1012,#955,#1053,.T.);
#1055=ORIENTED_EDGE('',*,*,#1054,.T.);
#1056=ORIENTED_EDGE('',*,*,#956,.F.);
#1057=EDGE_LOOP('',(#1010,#1014,#1055,#1056));
#1058=FACE_BOUND('',#1057,.T.);
#1059=ADVANCED_FACE('F307',(#1058),#23,.F.);
#1060=ORIENTED_EDGE('',*,*,#1013,.F.);
#1061=CARTESIAN_POINT('',(6.5467060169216,7.72330133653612,9.66697769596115));
#1062=CARTESIAN_POINT('',(6.64591288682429,7.58492422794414,9.66416255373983));
#1063=CARTESIAN_POINT('',(6.74799440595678,7.44862247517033,9.66190073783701));
#1064=CARTESIAN_POINT('',(6.95774811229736,7.18037757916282,9.65844214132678));
#1065=CARTESIAN_POINT('',(7.06542027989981,7.04843442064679,9.65724535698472));
#1066=CARTESIAN_POINT('',(7.39653737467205,6.65951022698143,9.65519040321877));
#1067=CARTESIAN_POINT('',(7.62812663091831,6.4093734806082,9.65586643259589));
#1068=CARTESIAN_POINT('',(8.11129299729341,5.92925394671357,9.66138002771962));
#1069=CARTESIAN_POINT('',(8.36287299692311,5.69927408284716,9.66621819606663));
#1070=CARTESIAN_POINT('',(8.88421895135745,5.26109545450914,9.68055080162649));
#1071=CARTESIAN_POINT('',(9.15398440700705,5.05289609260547,9.69004511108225));
#1072=CARTESIAN_POINT('',(9.70731186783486,4.66146851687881,9.71434109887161));
#1073=CARTESIAN_POINT('',(9.99073342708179,4.47803881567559,9.72909588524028));
#1074=CARTESIAN_POINT('',(10.5714417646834,4.13530031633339,9.764732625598));
#1075=CARTESIAN_POINT('',(10.8687285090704,3.97599145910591,9.78561456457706));
#1076=CARTESIAN_POINT('',(11.4746831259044,3.68269992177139,9.83420440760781));
#1077=CARTESIAN_POINT('',(11.7833407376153,3.54869504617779,9.86190627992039));
#1078=CARTESIAN_POINT('',(12.4099583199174,3.30668939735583,9.92468529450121));
#1079=CARTESIAN_POINT('',(12.7279182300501,3.19868845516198,9.95976238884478));
#1080=CARTESIAN_POINT('',(13.370278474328,3.00943594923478,10.0375625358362));
#1081=CARTESIAN_POINT('',(13.6946688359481,2.92814595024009,10.080274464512));
#1082=CARTESIAN_POINT('',(14.3479208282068,2.7924555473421,10.173495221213));
#1083=CARTESIAN_POINT('',(14.6767824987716,2.73805538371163,10.2240041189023));
#1084=CARTESIAN_POINT('',(15.3369192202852,2.65620760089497,10.3328061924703));
#1085=CARTESIAN_POINT('',(15.66819644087,2.62878831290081,10.391107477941));
#1086=CARTESIAN_POINT('',(16.3304789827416,2.60086726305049,10.5152293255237));
#1087=CARTESIAN_POINT('',(16.6614842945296,2.60036640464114,10.5810501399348));
#1088=CARTESIAN_POINT('',(17.3240428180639,2.62605289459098,10.7205107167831));
#1089=CARTESIAN_POINT('',(17.655572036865,2.65249066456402,10.7942180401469));
#1090=CARTESIAN_POINT('',(18.3138495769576,2.73187573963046,10.9484805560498));
#1091=CARTESIAN_POINT('',(18.6405974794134,2.78482535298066,11.0290363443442));
#1092=CARTESIAN_POINT('',(19.2867879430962,2.91642655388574,11.1963521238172));
#1093=CARTESIAN_POINT('',(19.6062391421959,2.99504586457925,11.2831042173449));
#1094=CARTESIAN_POINT('',(20.2362844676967,3.177089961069,11.4622866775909));
#1095=CARTESIAN_POINT('',(20.5468805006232,3.28050936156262,11.5547158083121));
#1096=CARTESIAN_POINT('',(20.8521318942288,3.39588894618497,11.6496949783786));
#1097=B_SPLINE_CURVE_WITH_KNOTS('',3,(#1061,#1062,#1063,#1064,#1065,#1066,#1067,#1068,#1069,
#1070,#1071,#1072,#1073,#1074,#1075,#1076,#1077,#1078,#1079,#1080,#1081,#1082,#1083,#1084,#1085,
#1086,#1087,#1088,#1089,#1090,#1091,#1092,#1093,#1094,#1095,#1096),.UNSPECIFIED.,.F.,.F.,(4,2,2,
2,2,2,2,2,2,2,2,2,2,2,2,2,2,4),(0.,0.510785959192,1.02157012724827,2.04291399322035,
3.06440575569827,4.0858694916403,5.09844663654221,6.11102130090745,7.12270361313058,
8.13437935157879,9.14459291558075,10.1548155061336,11.1660977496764,12.1774139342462,
13.1982178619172,14.2191106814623,15.2387247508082,16.2581176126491),.UNSPECIFIED.);
#1098=CARTESIAN_POINT('',(17.2513916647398,2.62600423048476,10.7060191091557));
#1099=VERTEX_POINT('',#1098);
#1100=EDGE_CURVE('E289',#1008,#1099,#1097,.T.);
#1101=ORIENTED_EDGE('',*,*,#1100,.T.);
#1102=CARTESIAN_POINT('',(28.542058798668,3.86093353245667,14.6248916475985));
#1103=CARTESIAN_POINT('',(28.0949251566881,3.78973654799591,14.4056959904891));
#1104=CARTESIAN_POINT('',(27.644194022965,3.72065339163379,14.1932196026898));
#1105=CARTESIAN_POINT('',(26.7359054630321,3.58698745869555,13.7818878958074));
#1106=CARTESIAN_POINT('',(26.2783480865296,3.52240464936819,13.583032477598));
#1107=CARTESIAN_POINT('',(24.8998297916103,3.33633398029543,13.0087706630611));
#1108=CARTESIAN_POINT('',(23.9692804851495,3.22192463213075,12.6538347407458));
#1109=CARTESIAN_POINT('',(22.0863023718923,3.01405683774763,12.0002442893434));
#1110=CARTESIAN_POINT('',(21.1338732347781,2.92059870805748,11.701590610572));
#1111=CARTESIAN_POINT('',(19.6898454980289,2.79722984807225,11.296179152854));
#1112=CARTESIAN_POINT('',(19.2049108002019,2.75884755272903,11.1679139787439));
#1113=CARTESIAN_POINT('',(18.2309836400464,2.68796520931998,10.9259763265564));
#1114=CARTESIAN_POINT('',(17.7419911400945,2.65546521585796,10.8123039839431));
#1115=CARTESIAN_POINT('',(17.2511916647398,2.62599221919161,10.7059757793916));
#1116=B_SPLINE_CURVE_WITH_KNOTS('',3,(#1102,#1103,#1104,#1105,#1106,#1107,#1108,#1109,#1110,
#1111,#1112,#1113,#1114,#1115),.UNSPECIFIED.,.F.,.F.,(4,2,2,2,2,2,4),(0.,1.508982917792,
3.01795485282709,6.02329086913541,9.0286722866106,10.537674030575,12.0466897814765),.UNSPECIFIED.);
#1117=EDGE_CURVE('E398',#543,#1099,#1116,.T.);
#1118=ORIENTED_EDGE('',*,*,#1117,.F.);
#1119=ORIENTED_EDGE('',*,*,#637,.T.);
#1120=CARTESIAN_POINT('',(28.542058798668,-3.86093353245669,14.6248916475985));
#1121=CARTESIAN_POINT('',(28.0949251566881,-3.78973654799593,14.4056959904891));
#1122=CARTESIAN_POINT('',(27.644194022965,-3.7206533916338,14.1932196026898));
#1123=CARTESIAN_POINT('',(26.7359054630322,-3.58698745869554,13.7818878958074));
#1124=CARTESIAN_POINT('',(26.2783480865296,-3.52240464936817,13.583032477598));
#1125=CARTESIAN_POINT('',(24.8998297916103,-3.3363339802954,13.0087706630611));
#1126=CARTESIAN_POINT('',(23.9692804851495,-3.22192463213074,12.6538347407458));
#1127=CARTESIAN_POINT('',(22.0863023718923,-3.01405683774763,12.0002442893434));
#1128=CARTESIAN_POINT('',(21.1338732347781,-2.92059870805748,11.701590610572));
#1129=CARTESIAN_POINT('',(19.6898454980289,-2.79722984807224,11.296179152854));
#1130=CARTESIAN_POINT('',(19.2049108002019,-2.75884755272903,11.1679139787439));
#1131=CARTESIAN_POINT('',(18.2309836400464,-2.68796520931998,10.9259763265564));
#1132=CARTESIAN_POINT('',(17.7419911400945,-2.65546521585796,10.8123039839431));
#1133=CARTESIAN_POINT('',(17.2511916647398,-2.62599221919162,10.7059757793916));
#1134=B_SPLINE_CURVE_WITH_KNOTS('',3,(#1120,#1121,#1122,#1123,#1124,#1125,#1126,#1127,#1128,
#1129,#1130,#1131,#1132,#1133),.UNSPECIFIED.,.F.,.F.,(4,2,2,2,2,2,4),(0.,1.508982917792,
3.0179548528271,6.02329086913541,9.0286722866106,10.537674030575,12.0466897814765),.UNSPECIFIED.);
#1135=CARTESIAN_POINT('',(17.2513916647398,-2.62600423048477,10.7060191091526));
#1136=VERTEX_POINT('',#1135);
#1137=EDGE_CURVE('E408',#634,#1136,#1134,.T.);
#1138=ORIENTED_EDGE('',*,*,#1137,.T.);
#1139=CARTESIAN_POINT('',(6.5467060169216,-7.72330133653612,9.66697769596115));
#1140=CARTESIAN_POINT('',(6.64591288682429,-7.58492422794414,9.66416255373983));
#1141=CARTESIAN_POINT('',(6.74799440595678,-7.44862247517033,9.66190073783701));
#1142=CARTESIAN_POINT('',(6.95774811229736,-7.18037757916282,9.65844214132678));
#1143=CARTESIAN_POINT('',(7.06542027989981,-7.04843442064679,9.65724535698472));
#1144=CARTESIAN_POINT('',(7.39653737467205,-6.65951022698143,9.65519040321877));
#1145=CARTESIAN_POINT('',(7.62812663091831,-6.4093734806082,9.65586643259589));
#1146=CARTESIAN_POINT('',(8.11129299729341,-5.92925394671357,9.66138002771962));
#1147=CARTESIAN_POINT('',(8.36287299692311,-5.69927408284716,9.66621819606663));
#1148=CARTESIAN_POINT('',(8.88421895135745,-5.26109545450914,9.68055080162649));
#1149=CARTESIAN_POINT('',(9.15398440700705,-5.05289609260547,9.69004511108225));
#1150=CARTESIAN_POINT('',(9.70731186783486,-4.66146851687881,9.71434109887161));
#1151=CARTESIAN_POINT('',(9.99073342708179,-4.47803881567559,9.72909588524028));
#1152=CARTESIAN_POINT('',(10.5714417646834,-4.13530031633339,9.764732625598));
#1153=CARTESIAN_POINT('',(10.8687285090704,-3.97599145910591,9.78561456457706));
#1154=CARTESIAN_POINT('',(11.4746831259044,-3.68269992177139,9.83420440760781));
#1155=CARTESIAN_POINT('',(11.7833407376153,-3.54869504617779,9.86190627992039));
#1156=CARTESIAN_POINT('',(12.4099583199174,-3.30668939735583,9.92468529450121));
#1157=CARTESIAN_POINT('',(12.7279182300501,-3.19868845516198,9.95976238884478));
#1158=CARTESIAN_POINT('',(13.370278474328,-3.00943594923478,10.0375625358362));
#1159=CARTESIAN_POINT('',(13.6946688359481,-2.92814595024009,10.080274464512));
#1160=CARTESIAN_POINT('',(14.3479208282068,-2.7924555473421,10.173495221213));
#1161=CARTESIAN_POINT('',(14.6767824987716,-2.73805538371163,10.2240041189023));
#1162=CARTESIAN_POINT('',(15.3369192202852,-2.65620760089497,10.3328061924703));
#1163=CARTESIAN_POINT('',(15.66819644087,-2.62878831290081,10.391107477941));
#1164=CARTESIAN_POINT('',(16.3304789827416,-2.60086726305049,10.5152293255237));
#1165=CARTESIAN_POINT('',(16.6614842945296,-2.60036640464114,10.5810501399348));
#1166=CARTESIAN_POINT('',(17.3240428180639,-2.62605289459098,10.7205107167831));
#1167=CARTESIAN_POINT('',(17.655572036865,-2.65249066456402,10.7942180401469));
#1168=CARTESIAN_POINT('',(18.3138495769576,-2.73187573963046,10.9484805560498));
#1169=CARTESIAN_POINT('',(18.6405974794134,-2.78482535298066,11.0290363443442));
#1170=CARTESIAN_POINT('',(19.2867879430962,-2.91642655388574,11.1963521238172));
#1171=CARTESIAN_POINT('',(19.6062391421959,-2.99504586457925,11.2831042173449));
#1172=CARTESIAN_POINT('',(20.2362844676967,-3.177089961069,11.4622866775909));
#1173=CARTESIAN_POINT('',(20.5468805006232,-3.28050936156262,11.5547158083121));
#1174=CARTESIAN_POINT('',(20.8521318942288,-3.39588894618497,11.6496949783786));
#1175=B_SPLINE_CURVE_WITH_KNOTS('',3,(#1139,#1140,#1141,#1142,#1143,#1144,#1145,#1146,#1147,
#1148,#1149,#1150,#1151,#1152,#1153,#1154,#1155,#1156,#1157,#1158,#1159,#1160,#1161,#1162,#1163,
#1164,#1165,#1166,#1167,#1168,#1169,#1170,#1171,#1172,#1173,#1174),.UNSPECIFIED.,.F.,.F.,(4,2,2,
2,2,2,2,2,2,2,2,2,2,2,2,2,2,4),(0.,0.510785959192,1.02157012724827,2.04291399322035,
3.06440575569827,4.0858694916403,5.09844663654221,6.11102130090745,7.12270361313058,
8.13437935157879,9.14459291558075,10.1548155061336,11.1660977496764,12.1774139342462,
13.1982178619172,14.2191106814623,15.2387247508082,16.2581176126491),.UNSPECIFIED.);
#1176=EDGE_CURVE('E170',#1012,#1136,#1175,.T.);
#1177=ORIENTED_EDGE('',*,*,#1176,.F.);
#1178=EDGE_LOOP('',(#1060,#1101,#1118,#1119,#1138,#1177));
#1179=FACE_BOUND('',#1178,.T.);
#1180=ADVANCED_FACE('F185',(#1179),#135,.T.);
#1181=CARTESIAN_POINT('',(-10.2946161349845,-118.46157794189,-6.26382242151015));
#1182=DIRECTION('',(0.,0.,1.));
#1183=DIRECTION('',(0.,-1.,0.));
#1184=AXIS2_PLACEMENT_3D('',#1181,#1182,#1183);
#1185=CYLINDRICAL_SURFACE('',#1184,116.044288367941);
#1186=DIRECTION('',(0.,0.,1.));
#1187=VECTOR('',#1186,1.);
#1188=CARTESIAN_POINT('',(-17.2513916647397,-2.62600423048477,-6.26382242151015));
#1189=LINE('',#1188,#1187);
#1190=CARTESIAN_POINT('',(-17.2513916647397,-2.62600423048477,21.0375722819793));
#1191=VERTEX_POINT('',#1190);
#1192=EDGE_CURVE('E164',#175,#1191,#1189,.T.);
#1193=ORIENTED_EDGE('',*,*,#1192,.T.);
#1194=CARTESIAN_POINT('',(-17.2511916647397,-2.62599221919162,21.0379050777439));
#1195=CARTESIAN_POINT('',(-17.360550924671,-2.63256021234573,20.8558730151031));
#1196=CARTESIAN_POINT('',(-17.4781769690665,-2.63977928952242,20.678886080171));
#1197=CARTESIAN_POINT('',(-17.7285891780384,-2.65558215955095,20.3361701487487));
#1198=CARTESIAN_POINT('',(-17.8613680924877,-2.66416530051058,20.1704358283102));
#1199=CARTESIAN_POINT('',(-18.1403342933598,-2.68273269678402,19.8517713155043));
#1200=CARTESIAN_POINT('',(-18.286473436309,-2.69271198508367,19.6987986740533));
#1201=CARTESIAN_POINT('',(-18.5911387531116,-2.71414613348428,19.4059031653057));
#1202=CARTESIAN_POINT('',(-18.7496661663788,-2.72560114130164,19.2659816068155));
#1203=CARTESIAN_POINT('',(-19.2412701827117,-2.76221931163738,18.8673844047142));
#1204=CARTESIAN_POINT('',(-19.5910610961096,-2.78968031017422,18.6290924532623));
#1205=CARTESIAN_POINT('',(-20.323832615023,-2.85090757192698,18.2118100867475));
#1206=CARTESIAN_POINT('',(-20.7068386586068,-2.88467869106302,18.0328656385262));
#1207=CARTESIAN_POINT('',(-21.5122385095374,-2.96001104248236,17.7306832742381));
#1208=CARTESIAN_POINT('',(-21.9356131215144,-3.00184137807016,17.6101220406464));
#1209=CARTESIAN_POINT('',(-22.7954871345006,-3.09177206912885,17.4380525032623));
#1210=CARTESIAN_POINT('',(-23.2319888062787,-3.13987351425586,17.3865562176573));
#1211=CARTESIAN_POINT('',(-24.1298090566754,-3.24404995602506,17.3524127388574));
#1212=CARTESIAN_POINT('',(-24.5912401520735,-3.30040917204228,17.3734764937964));
#1213=CARTESIAN_POINT('',(-25.5036209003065,-3.41734859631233,17.492493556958));
#1214=CARTESIAN_POINT('',(-25.9545689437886,-3.47792944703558,17.5904585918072));
#1215=CARTESIAN_POINT('',(-26.8360894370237,-3.60141943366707,17.8628288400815));
#1216=CARTESIAN_POINT('',(-27.2664963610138,-3.6643419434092,18.0377665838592));
#1217=CARTESIAN_POINT('',(-28.0897613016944,-3.7890743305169,18.4612298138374));
#1218=CARTESIAN_POINT('',(-28.4826254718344,-3.8508843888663,18.7097432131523));
#1219=CARTESIAN_POINT('',(-29.2009277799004,-3.96723220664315,19.2630368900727));
#1220=CARTESIAN_POINT('',(-29.5285296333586,-4.02196785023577,19.5649593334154));
#1221=CARTESIAN_POINT('',(-30.1237087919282,-4.12359078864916,20.2242762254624));
#1222=CARTESIAN_POINT('',(-30.3913170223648,-4.17048212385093,20.5816419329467));
#1223=CARTESIAN_POINT('',(-30.8373181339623,-4.24983645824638,21.3128397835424));
#1224=CARTESIAN_POINT('',(-31.0209063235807,-4.28311924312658,21.6834132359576));
#1225=CARTESIAN_POINT('',(-31.3188213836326,-4.33759779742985,22.4522485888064));
#1226=CARTESIAN_POINT('',(-31.4331834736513,-4.35879971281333,22.8504962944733));
#1227=CARTESIAN_POINT('',(-31.5819417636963,-4.38646265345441,23.6329821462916));
#1228=CARTESIAN_POINT('',(-31.6214051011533,-4.3938571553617,24.0162299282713));
#1229=CARTESIAN_POINT('',(-31.634312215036,-4.39627063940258,24.7838358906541));
#1230=CARTESIAN_POINT('',(-31.6077711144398,-4.39129245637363,25.16819379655));
#1231=CARTESIAN_POINT('',(-31.4916539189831,-4.36966021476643,25.9147246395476));
#1232=CARTESIAN_POINT('',(-31.4040395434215,-4.35336958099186,26.2772163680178));
#1233=CARTESIAN_POINT('',(-31.171301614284,-4.31056061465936,26.9825464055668));
#1234=CARTESIAN_POINT('',(-31.0261753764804,-4.28404180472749,27.3253837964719));
#1235=CARTESIAN_POINT('',(-30.6801290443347,-4.22174644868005,27.9896317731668));
#1236=CARTESIAN_POINT('',(-30.4781308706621,-4.18579203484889,28.3104623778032));
#1237=CARTESIAN_POINT('',(-30.026522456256,-4.10694895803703,28.9156211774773));
#1238=CARTESIAN_POINT('',(-29.7769013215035,-4.06405870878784,29.1999409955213));
#1239=CARTESIAN_POINT('',(-29.2214742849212,-3.97081569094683,29.7422665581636));
#1240=CARTESIAN_POINT('',(-28.9132096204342,-3.92017079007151,29.9977012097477));
#1241=CARTESIAN_POINT('',(-28.2607761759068,-3.81602372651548,30.4568418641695));
#1242=CARTESIAN_POINT('',(-27.9165957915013,-3.76252064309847,30.6605310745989));
#1243=CARTESIAN_POINT('',(-27.1748146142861,-3.65092338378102,31.0261640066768));
#1244=CARTESIAN_POINT('',(-26.7751452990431,-3.59278264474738,31.1838989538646));
#1245=CARTESIAN_POINT('',(-25.9555667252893,-3.47817566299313,31.4338219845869));
#1246=CARTESIAN_POINT('',(-25.535651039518,-3.42170996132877,31.5259891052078));
#1247=CARTESIAN_POINT('',(-24.6605018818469,-3.30905170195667,31.647128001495));
#1248=CARTESIAN_POINT('',(-24.2046656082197,-3.25308093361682,31.6719539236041));
#1249=CARTESIAN_POINT('',(-23.2941812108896,-3.14680042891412,31.6461183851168));
#1250=CARTESIAN_POINT('',(-22.8395332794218,-3.09649155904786,31.595445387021));
#1251=CARTESIAN_POINT('',(-22.1635402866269,-3.0256264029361,31.4625458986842));
#1252=CARTESIAN_POINT('',(-21.9367328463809,-3.00254244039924,31.4078302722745));
#1253=CARTESIAN_POINT('',(-21.4884958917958,-2.9582253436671,31.279126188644));
#1254=CARTESIAN_POINT('',(-21.2670643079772,-2.93699148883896,31.2051452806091));
#1255=CARTESIAN_POINT('',(-20.8311241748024,-2.89641504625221,31.0381373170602));
#1256=CARTESIAN_POINT('',(-20.6166214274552,-2.87707401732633,30.9450947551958));
#1257=CARTESIAN_POINT('',(-20.1965861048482,-2.84033307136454,30.7404574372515));
#1258=CARTESIAN_POINT('',(-19.9910494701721,-2.82293227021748,30.6288711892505));
#1259=CARTESIAN_POINT('',(-19.5960776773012,-2.79050166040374,30.3909216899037));
#1260=CARTESIAN_POINT('',(-19.4063577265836,-2.77542055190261,30.2650383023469));
#1261=CARTESIAN_POINT('',(-19.0388353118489,-2.74706092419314,29.9969053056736));
#1262=CARTESIAN_POINT('',(-18.8610271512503,-2.73378154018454,29.8546636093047));
#1263=CARTESIAN_POINT('',(-18.5192661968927,-2.70899133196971,29.5548548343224));
#1264=CARTESIAN_POINT('',(-18.355289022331,-2.69747736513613,29.3973158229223));
#1265=CARTESIAN_POINT('',(-18.0426182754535,-2.67613037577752,29.0677691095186));
#1266=CARTESIAN_POINT('',(-17.8939151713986,-2.66629630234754,28.8957705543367));
#1267=CARTESIAN_POINT('',(-17.6624475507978,-2.65138715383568,28.6009730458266));
#1268=CARTESIAN_POINT('',(-17.5748056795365,-2.64585026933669,28.4819960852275));
#1269=CARTESIAN_POINT('',(-17.4071874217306,-2.6354357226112,28.238951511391));
#1270=CARTESIAN_POINT('',(-17.3272016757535,-2.63055725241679,28.1148903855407));
#1271=CARTESIAN_POINT('',(-17.2511916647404,-2.62599221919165,27.988395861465));
#1272=B_SPLINE_CURVE_WITH_KNOTS('',3,(#1194,#1195,#1196,#1197,#1198,#1199,#1200,#1201,#1202,
#1203,#1204,#1205,#1206,#1207,#1208,#1209,#1210,#1211,#1212,#1213,#1214,#1215,#1216,#1217,#1218,
#1219,#1220,#1221,#1222,#1223,#1224,#1225,#1226,#1227,#1228,#1229,#1230,#1231,#1232,#1233,#1234,
#1235,#1236,#1237,#1238,#1239,#1240,#1241,#1242,#1243,#1244,#1245,#1246,#1247,#1248,#1249,#1250,
#1251,#1252,#1253,#1254,#1255,#1256,#1257,#1258,#1259,#1260,#1261,#1262,#1263,#1264,#1265,#1266,
#1267,#1268,#1269,#1270,#1271),.UNSPECIFIED.,.F.,.F.,(4,2,2,2,2,2,2,2,2,2,2,2,2,2,2,2,2,2,2,2,2,
2,2,2,2,2,2,2,2,2,2,2,2,2,2,2,2,2,4),(0.,0.63708187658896,1.27386019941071,1.90842811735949,
2.54305960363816,3.80922160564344,5.07636201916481,6.39710448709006,7.71807675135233,
9.10758912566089,10.4973134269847,11.896807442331,13.2960716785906,14.6355489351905,
15.9743341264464,17.2124522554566,18.4499399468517,19.6002244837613,20.750245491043,
21.8649336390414,22.9796738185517,24.117160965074,25.2549086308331,26.4603303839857,
27.6661428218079,28.9612559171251,30.2567828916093,31.6304309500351,33.0042889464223,
33.7069364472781,34.4093090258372,35.1122552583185,35.8148798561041,36.4985491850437,
37.1818891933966,37.8639982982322,38.5456791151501,38.989039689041,39.4318511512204),.UNSPECIFIED.);
#1273=CARTESIAN_POINT('',(-17.2513916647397,-2.62600423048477,27.9887286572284));
#1274=VERTEX_POINT('',#1273);
#1275=EDGE_CURVE('E40',#1191,#1274,#1272,.T.);
#1276=ORIENTED_EDGE('',*,*,#1275,.T.);
#1277=EDGE_CURVE('E158',#1274,#675,#1189,.T.);
#1278=ORIENTED_EDGE('',*,*,#1277,.T.);
#1279=ORIENTED_EDGE('',*,*,#676,.F.);
#1280=ORIENTED_EDGE('',*,*,#357,.T.);
#1281=ORIENTED_EDGE('',*,*,#195,.T.);
#1282=EDGE_LOOP('',(#1193,#1276,#1278,#1279,#1280,#1281));
#1283=FACE_BOUND('',#1282,.T.);
#1284=ADVANCED_FACE('F343',(#1283),#1185,.F.);
#1285=CARTESIAN_POINT('',(-16.5160135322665,-14.8706062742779,-6.26382242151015));
#1286=DIRECTION('',(0.,0.,1.));
#1287=DIRECTION('',(0.,-1.,0.));
#1288=AXIS2_PLACEMENT_3D('',#1285,#1286,#1287);
#1289=CYLINDRICAL_SURFACE('',#1288,12.2666645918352);
#1290=CARTESIAN_POINT('',(-17.2515916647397,-2.62601624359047,21.0372395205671));
#1291=CARTESIAN_POINT('',(-17.1553838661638,-2.62022150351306,21.1974244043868));
#1292=CARTESIAN_POINT('',(-17.0632330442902,-2.61583941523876,21.3600342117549));
#1293=CARTESIAN_POINT('',(-16.888739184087,-2.60929797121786,21.6909196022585));
#1294=CARTESIAN_POINT('',(-16.8064184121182,-2.60714358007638,21.8592069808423));
#1295=CARTESIAN_POINT('',(-16.5760436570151,-2.60311809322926,22.3757154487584));
#1296=CARTESIAN_POINT('',(-16.4463279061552,-2.60376545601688,22.7327987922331));
#1297=CARTESIAN_POINT('',(-16.3111238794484,-2.60558962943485,23.2492659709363));
#1298=CARTESIAN_POINT('',(-16.2774293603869,-2.60623171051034,23.401507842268));
#1299=CARTESIAN_POINT('',(-16.2226438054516,-2.60741948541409,23.7082136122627));
#1300=CARTESIAN_POINT('',(-16.2015461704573,-2.60796522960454,23.8626763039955));
#1301=CARTESIAN_POINT('',(-16.1728384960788,-2.60873412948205,24.1720064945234));
#1302=CARTESIAN_POINT('',(-16.1651549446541,-2.60895904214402,24.3268670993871));
#1303=CARTESIAN_POINT('',(-16.1633150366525,-2.60901456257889,24.6366432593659));
#1304=CARTESIAN_POINT('',(-16.1691588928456,-2.60884516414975,24.791558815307));
#1305=CARTESIAN_POINT('',(-16.2067663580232,-2.60780469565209,25.254174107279));
#1306=CARTESIAN_POINT('',(-16.2585447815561,-2.60640291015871,25.5604124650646));
#1307=CARTESIAN_POINT('',(-16.408677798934,-2.6041929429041,26.1623826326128));
#1308=CARTESIAN_POINT('',(-16.5072746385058,-2.60338790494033,26.4580510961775));
#1309=CARTESIAN_POINT('',(-16.7113723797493,-2.60518732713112,26.962632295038));
#1310=CARTESIAN_POINT('',(-16.8090508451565,-2.60699326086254,27.1748260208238));
#1311=CARTESIAN_POINT('',(-17.0197513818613,-2.61383210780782,27.5889785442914));
#1312=CARTESIAN_POINT('',(-17.1326231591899,-2.61883501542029,27.7910138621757));
#1313=CARTESIAN_POINT('',(-17.2515916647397,-2.62601624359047,27.9890614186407));
#1314=B_SPLINE_CURVE_WITH_KNOTS('',3,(#1290,#1291,#1292,#1293,#1294,#1295,#1296,#1297,#1298,
#1299,#1300,#1301,#1302,#1303,#1304,#1305,#1306,#1307,#1308,#1309,#1310,#1311,#1312,#1313),
.UNSPECIFIED.,.F.,.F.,(4,2,2,2,2,2,2,2,2,2,2,4),(0.,0.560608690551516,1.12246406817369,
2.25597729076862,2.72334272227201,3.19046310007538,3.65501542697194,4.11957506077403,
5.04670400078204,5.97868320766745,6.67876235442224,7.37236544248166),.UNSPECIFIED.);
#1315=EDGE_CURVE('E28',#1191,#1274,#1314,.T.);
#1316=ORIENTED_EDGE('',*,*,#1315,.F.);
#1317=ORIENTED_EDGE('',*,*,#1192,.F.);
#1318=ORIENTED_EDGE('',*,*,#176,.F.);
#1319=ORIENTED_EDGE('',*,*,#67,.T.);
#1320=ORIENTED_EDGE('',*,*,#936,.T.);
#1321=ORIENTED_EDGE('',*,*,#705,.T.);
#1322=ORIENTED_EDGE('',*,*,#1277,.F.);
#1323=EDGE_LOOP('',(#1316,#1317,#1318,#1319,#1320,#1321,#1322));
#1324=FACE_BOUND('',#1323,.T.);
#1325=ADVANCED_FACE('F194',(#1324),#1289,.F.);
#1326=CARTESIAN_POINT('',(16.5160135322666,-14.8706062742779,-6.26382242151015));
#1327=DIRECTION('',(0.,0.,1.));
#1328=DIRECTION('',(0.,-1.,0.));
#1329=AXIS2_PLACEMENT_3D('',#1326,#1327,#1328);
#1330=CYLINDRICAL_SURFACE('',#1329,12.2666645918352);
#1331=DIRECTION('',(0.,0.,1.));
#1332=VECTOR('',#1331,1.);
#1333=CARTESIAN_POINT('',(17.2513916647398,-2.62600423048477,-6.26382242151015));
#1334=LINE('',#1333,#1332);
#1335=CARTESIAN_POINT('',(17.2513916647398,-2.62600423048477,21.0375722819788));
#1336=VERTEX_POINT('',#1335);
#1337=EDGE_CURVE('E233',#1136,#1336,#1334,.T.);
#1338=ORIENTED_EDGE('',*,*,#1337,.T.);
#1339=CARTESIAN_POINT('',(17.2515916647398,-2.62601624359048,21.0372395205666));
#1340=CARTESIAN_POINT('',(17.155383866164,-2.62022150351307,21.1974244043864));
#1341=CARTESIAN_POINT('',(17.0632330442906,-2.61583941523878,21.3600342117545));
#1342=CARTESIAN_POINT('',(16.8887391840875,-2.60929797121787,21.6909196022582));
#1343=CARTESIAN_POINT('',(16.8064184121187,-2.60714358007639,21.8592069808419));
#1344=CARTESIAN_POINT('',(16.5760436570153,-2.60311809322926,22.3757154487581));
#1345=CARTESIAN_POINT('',(16.4463279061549,-2.60376545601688,22.7327987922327));
#1346=CARTESIAN_POINT('',(16.3111238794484,-2.60558962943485,23.2492659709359));
#1347=CARTESIAN_POINT('',(16.2774293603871,-2.60623171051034,23.4015078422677));
#1348=CARTESIAN_POINT('',(16.2226438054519,-2.60741948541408,23.7082136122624));
#1349=CARTESIAN_POINT('',(16.2015461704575,-2.60796522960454,23.8626763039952));
#1350=CARTESIAN_POINT('',(16.1728384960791,-2.60873412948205,24.1720064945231));
#1351=CARTESIAN_POINT('',(16.1651549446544,-2.60895904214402,24.3268670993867));
#1352=CARTESIAN_POINT('',(16.1633150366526,-2.60901456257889,24.6366432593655));
#1353=CARTESIAN_POINT('',(16.1691588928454,-2.60884516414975,24.7915588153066));
#1354=CARTESIAN_POINT('',(16.2067663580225,-2.60780469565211,25.2541741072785));
#1355=CARTESIAN_POINT('',(16.2585447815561,-2.60640291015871,25.560412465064));
#1356=CARTESIAN_POINT('',(16.4086777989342,-2.60419294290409,26.1623826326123));
#1357=CARTESIAN_POINT('',(16.5072746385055,-2.60338790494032,26.4580510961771));
#1358=CARTESIAN_POINT('',(16.711372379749,-2.60518732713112,26.9626322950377));
#1359=CARTESIAN_POINT('',(16.8090508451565,-2.60699326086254,27.1748260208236));
#1360=CARTESIAN_POINT('',(17.0197513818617,-2.61383210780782,27.5889785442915));
#1361=CARTESIAN_POINT('',(17.1326231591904,-2.6188350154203,27.7910138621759));
#1362=CARTESIAN_POINT('',(17.2515916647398,-2.62601624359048,27.9890614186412));
#1363=B_SPLINE_CURVE_WITH_KNOTS('',3,(#1339,#1340,#1341,#1342,#1343,#1344,#1345,#1346,#1347,
#1348,#1349,#1350,#1351,#1352,#1353,#1354,#1355,#1356,#1357,#1358,#1359,#1360,#1361,#1362),
.UNSPECIFIED.,.F.,.F.,(4,2,2,2,2,2,2,2,2,2,2,4),(0.,0.560608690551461,1.12246406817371,
2.25597729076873,2.7233427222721,3.19046310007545,3.65501542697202,4.11957506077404,
5.046704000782,5.97868320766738,6.67876235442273,7.37236544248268),.UNSPECIFIED.);
#1364=CARTESIAN_POINT('',(17.2513916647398,-2.62600423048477,27.988728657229));
#1365=VERTEX_POINT('',#1364);
#1366=EDGE_CURVE('E214',#1336,#1365,#1363,.T.);
#1367=ORIENTED_EDGE('',*,*,#1366,.T.);
#1368=EDGE_CURVE('E232',#1365,#742,#1334,.T.);
#1369=ORIENTED_EDGE('',*,*,#1368,.T.);
#1370=ORIENTED_EDGE('',*,*,#743,.F.);
#1371=ORIENTED_EDGE('',*,*,#962,.F.);
#1372=ORIENTED_EDGE('',*,*,#1054,.F.);
#1373=ORIENTED_EDGE('',*,*,#1176,.T.);
#1374=EDGE_LOOP('',(#1338,#1367,#1369,#1370,#1371,#1372,#1373));
#1375=FACE_BOUND('',#1374,.T.);
#1376=ADVANCED_FACE('F188',(#1375),#1330,.F.);
#1377=CARTESIAN_POINT('',(10.2946161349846,-118.46157794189,-6.26382242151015));
#1378=DIRECTION('',(0.,0.,1.));
#1379=DIRECTION('',(0.,-1.,0.));
#1380=AXIS2_PLACEMENT_3D('',#1377,#1378,#1379);
#1381=CYLINDRICAL_SURFACE('',#1380,116.044288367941);
#1382=CARTESIAN_POINT('',(17.2511916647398,-2.62599221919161,21.0379050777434));
#1383=CARTESIAN_POINT('',(17.3605509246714,-2.63256021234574,20.8558730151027));
#1384=CARTESIAN_POINT('',(17.4781769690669,-2.63977928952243,20.6788860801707));
#1385=CARTESIAN_POINT('',(17.7285891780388,-2.65558215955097,20.3361701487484));
#1386=CARTESIAN_POINT('',(17.8613680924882,-2.66416530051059,20.1704358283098));
#1387=CARTESIAN_POINT('',(18.1403342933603,-2.68273269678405,19.851771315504));
#1388=CARTESIAN_POINT('',(18.2864734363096,-2.69271198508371,19.6987986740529));
#1389=CARTESIAN_POINT('',(18.5911387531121,-2.71414613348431,19.4059031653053));
#1390=CARTESIAN_POINT('',(18.7496661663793,-2.72560114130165,19.265981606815));
#1391=CARTESIAN_POINT('',(19.2412701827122,-2.76221931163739,18.8673844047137));
#1392=CARTESIAN_POINT('',(19.5910610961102,-2.78968031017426,18.629092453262));
#1393=CARTESIAN_POINT('',(20.3238326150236,-2.85090757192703,18.2118100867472));
#1394=CARTESIAN_POINT('',(20.7068386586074,-2.88467869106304,18.0328656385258));
#1395=CARTESIAN_POINT('',(21.512238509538,-2.96001104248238,17.7306832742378));
#1396=CARTESIAN_POINT('',(21.9356131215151,-3.00184137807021,17.6101220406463));
#1397=CARTESIAN_POINT('',(22.7954871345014,-3.09177206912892,17.4380525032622));
#1398=CARTESIAN_POINT('',(23.2319888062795,-3.13987351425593,17.3865562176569));
#1399=CARTESIAN_POINT('',(24.1298090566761,-3.24404995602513,17.352412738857));
#1400=CARTESIAN_POINT('',(24.5912401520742,-3.30040917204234,17.3734764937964));
#1401=CARTESIAN_POINT('',(25.5036209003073,-3.41734859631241,17.4924935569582));
#1402=CARTESIAN_POINT('',(25.9545689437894,-3.47792944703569,17.5904585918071));
#1403=CARTESIAN_POINT('',(26.8360894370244,-3.60141943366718,17.8628288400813));
#1404=CARTESIAN_POINT('',(27.2664963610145,-3.66434194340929,18.0377665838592));
#1405=CARTESIAN_POINT('',(28.0897613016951,-3.789074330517,18.4612298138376));
#1406=CARTESIAN_POINT('',(28.4826254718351,-3.85088438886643,18.7097432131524));
#1407=CARTESIAN_POINT('',(29.2009277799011,-3.96723220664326,19.2630368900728));
#1408=CARTESIAN_POINT('',(29.5285296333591,-4.02196785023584,19.5649593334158));
#1409=CARTESIAN_POINT('',(30.1237087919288,-4.12359078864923,20.2242762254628));
#1410=CARTESIAN_POINT('',(30.3913170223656,-4.17048212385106,20.5816419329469));
#1411=CARTESIAN_POINT('',(30.8373181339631,-4.24983645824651,21.3128397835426));
#1412=CARTESIAN_POINT('',(31.0209063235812,-4.28311924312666,21.6834132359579));
#1413=CARTESIAN_POINT('',(31.318821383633,-4.33759779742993,22.4522485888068));
#1414=CARTESIAN_POINT('',(31.4331834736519,-4.35879971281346,22.8504962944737));
#1415=CARTESIAN_POINT('',(31.5819417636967,-4.38646265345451,23.632982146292));
#1416=CARTESIAN_POINT('',(31.6214051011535,-4.39385715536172,24.0162299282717));
#1417=CARTESIAN_POINT('',(31.6343122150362,-4.3962706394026,24.7838358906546));
#1418=CARTESIAN_POINT('',(31.6077711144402,-4.39129245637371,25.1681937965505));
#1419=CARTESIAN_POINT('',(31.4916539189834,-4.36966021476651,25.9147246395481));
#1420=CARTESIAN_POINT('',(31.4040395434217,-4.35336958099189,26.2772163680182));
#1421=CARTESIAN_POINT('',(31.1713016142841,-4.31056061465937,26.9825464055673));
#1422=CARTESIAN_POINT('',(31.0261753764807,-4.28404180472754,27.3253837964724));
#1423=CARTESIAN_POINT('',(30.680129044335,-4.22174644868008,27.9896317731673));
#1424=CARTESIAN_POINT('',(30.478130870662,-4.18579203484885,28.3104623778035));
#1425=CARTESIAN_POINT('',(30.0265224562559,-4.10694895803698,28.9156211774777));
#1426=CARTESIAN_POINT('',(29.7769013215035,-4.06405870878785,29.1999409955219));
#1427=CARTESIAN_POINT('',(29.2214742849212,-3.97081569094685,29.7422665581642));
#1428=CARTESIAN_POINT('',(28.913209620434,-3.92017079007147,29.9977012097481));
#1429=CARTESIAN_POINT('',(28.2607761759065,-3.81602372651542,30.4568418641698));
#1430=CARTESIAN_POINT('',(27.9165957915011,-3.76252064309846,30.6605310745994));
#1431=CARTESIAN_POINT('',(27.1748146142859,-3.65092338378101,31.0261640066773));
#1432=CARTESIAN_POINT('',(26.7751452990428,-3.59278264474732,31.1838989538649));
#1433=CARTESIAN_POINT('',(25.9555667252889,-3.47817566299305,31.4338219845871));
#1434=CARTESIAN_POINT('',(25.5356510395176,-3.42170996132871,31.5259891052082));
#1435=CARTESIAN_POINT('',(24.6605018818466,-3.30905170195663,31.6471280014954));
#1436=CARTESIAN_POINT('',(24.2046656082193,-3.25308093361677,31.6719539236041));
#1437=CARTESIAN_POINT('',(23.2941812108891,-3.14680042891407,31.6461183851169));
#1438=CARTESIAN_POINT('',(22.8395332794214,-3.09649155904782,31.5954453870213));
#1439=CARTESIAN_POINT('',(22.1635402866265,-3.02562640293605,31.4625458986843));
#1440=CARTESIAN_POINT('',(21.9367328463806,-3.00254244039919,31.4078302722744));
#1441=CARTESIAN_POINT('',(21.4884958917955,-2.95822534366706,31.2791261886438));
#1442=CARTESIAN_POINT('',(21.2670643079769,-2.93699148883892,31.2051452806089));
#1443=CARTESIAN_POINT('',(20.8311241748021,-2.89641504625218,31.03813731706));
#1444=CARTESIAN_POINT('',(20.6166214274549,-2.87707401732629,30.9450947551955));
#1445=CARTESIAN_POINT('',(20.1965861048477,-2.84033307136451,30.7404574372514));
#1446=CARTESIAN_POINT('',(19.9910494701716,-2.82293227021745,30.6288711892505));
#1447=CARTESIAN_POINT('',(19.5960776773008,-2.79050166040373,30.3909216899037));
#1448=CARTESIAN_POINT('',(19.4063577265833,-2.7754205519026,30.2650383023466));
#1449=CARTESIAN_POINT('',(19.0388353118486,-2.74706092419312,29.9969053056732));
#1450=CARTESIAN_POINT('',(18.8610271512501,-2.73378154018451,29.8546636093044));
#1451=CARTESIAN_POINT('',(18.5192661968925,-2.70899133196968,29.554854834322));
#1452=CARTESIAN_POINT('',(18.3552890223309,-2.69747736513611,29.3973158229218));
#1453=CARTESIAN_POINT('',(18.0426182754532,-2.6761303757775,29.0677691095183));
#1454=CARTESIAN_POINT('',(17.8939151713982,-2.66629630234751,28.8957705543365));
#1455=CARTESIAN_POINT('',(17.6624475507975,-2.65138715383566,28.6009730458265));
#1456=CARTESIAN_POINT('',(17.5748056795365,-2.64585026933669,28.4819960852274));
#1457=CARTESIAN_POINT('',(17.4071874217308,-2.63543572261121,28.238951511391));
#1458=CARTESIAN_POINT('',(17.3272016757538,-2.6305572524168,28.1148903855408));
#1459=CARTESIAN_POINT('',(17.2511916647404,-2.62599221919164,27.9883958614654));
#1460=B_SPLINE_CURVE_WITH_KNOTS('',3,(#1382,#1383,#1384,#1385,#1386,#1387,#1388,#1389,#1390,
#1391,#1392,#1393,#1394,#1395,#1396,#1397,#1398,#1399,#1400,#1401,#1402,#1403,#1404,#1405,#1406,
#1407,#1408,#1409,#1410,#1411,#1412,#1413,#1414,#1415,#1416,#1417,#1418,#1419,#1420,#1421,#1422,
#1423,#1424,#1425,#1426,#1427,#1428,#1429,#1430,#1431,#1432,#1433,#1434,#1435,#1436,#1437,#1438,
#1439,#1440,#1441,#1442,#1443,#1444,#1445,#1446,#1447,#1448,#1449,#1450,#1451,#1452,#1453,#1454,
#1455,#1456,#1457,#1458,#1459),.UNSPECIFIED.,.F.,.F.,(4,2,2,2,2,2,2,2,2,2,2,2,2,2,2,2,2,2,2,2,2,
2,2,2,2,2,2,2,2,2,2,2,2,2,2,2,2,2,4),(0.,0.637081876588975,1.27386019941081,1.90842811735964,
2.54305960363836,3.80922160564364,5.07636201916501,6.39710448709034,7.71807675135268,
9.10758912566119,10.497313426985,11.8968074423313,13.2960716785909,14.6355489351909,
15.9743341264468,17.212452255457,18.4499399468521,19.6002244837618,20.7502454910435,
21.8649336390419,22.9796738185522,24.1171609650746,25.2549086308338,26.4603303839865,
27.6661428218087,28.961255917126,30.2567828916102,31.630430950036,33.0042889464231,
33.7069364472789,34.4093090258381,35.1122552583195,35.814879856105,36.4985491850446,
37.1818891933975,37.8639982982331,38.5456791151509,38.9890396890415,39.4318511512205),.UNSPECIFIED.);
#1461=EDGE_CURVE('E354',#1336,#1365,#1460,.T.);
#1462=ORIENTED_EDGE('',*,*,#1461,.F.);
#1463=ORIENTED_EDGE('',*,*,#1337,.F.);
#1464=ORIENTED_EDGE('',*,*,#1137,.F.);
#1465=ORIENTED_EDGE('',*,*,#635,.F.);
#1466=ORIENTED_EDGE('',*,*,#756,.T.);
#1467=ORIENTED_EDGE('',*,*,#1368,.F.);
#1468=EDGE_LOOP('',(#1462,#1463,#1464,#1465,#1466,#1467));
#1469=FACE_BOUND('',#1468,.T.);
#1470=ADVANCED_FACE('F193',(#1469),#1381,.F.);
#1471=CARTESIAN_POINT('',(-16.5160135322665,14.8706062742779,-6.26382242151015));
#1472=DIRECTION('',(0.,0.,1.));
#1473=DIRECTION('',(0.,-1.,0.));
#1474=AXIS2_PLACEMENT_3D('',#1471,#1472,#1473);
#1475=CYLINDRICAL_SURFACE('',#1474,12.2666645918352);
#1476=DIRECTION('',(0.,0.,1.));
#1477=VECTOR('',#1476,1.);
#1478=CARTESIAN_POINT('',(-17.2513916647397,2.62600423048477,-6.26382242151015));
#1479=LINE('',#1478,#1477);
#1480=CARTESIAN_POINT('',(-17.2513916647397,2.62600423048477,21.0375722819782));
#1481=VERTEX_POINT('',#1480);
#1482=EDGE_CURVE('E150',#222,#1481,#1479,.T.);
#1483=ORIENTED_EDGE('',*,*,#1482,.T.);
#1484=CARTESIAN_POINT('',(-17.2515916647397,2.62601624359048,21.0372395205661));
#1485=CARTESIAN_POINT('',(-17.155383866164,2.62022150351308,21.1974244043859));
#1486=CARTESIAN_POINT('',(-17.0632330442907,2.61583941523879,21.3600342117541));
#1487=CARTESIAN_POINT('',(-16.8887391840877,2.60929797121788,21.6909196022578));
#1488=CARTESIAN_POINT('',(-16.8064184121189,2.60714358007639,21.8592069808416));
#1489=CARTESIAN_POINT('',(-16.5760436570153,2.60311809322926,22.3757154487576));
#1490=CARTESIAN_POINT('',(-16.4463279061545,2.60376545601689,22.7327987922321));
#1491=CARTESIAN_POINT('',(-16.3111238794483,2.60558962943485,23.2492659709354));
#1492=CARTESIAN_POINT('',(-16.2774293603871,2.60623171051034,23.4015078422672));
#1493=CARTESIAN_POINT('',(-16.222643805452,2.60741948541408,23.7082136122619));
#1494=CARTESIAN_POINT('',(-16.2015461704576,2.60796522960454,23.8626763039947));
#1495=CARTESIAN_POINT('',(-16.1728384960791,2.60873412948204,24.1720064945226));
#1496=CARTESIAN_POINT('',(-16.1651549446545,2.60895904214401,24.3268670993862));
#1497=CARTESIAN_POINT('',(-16.1633150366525,2.60901456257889,24.636643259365));
#1498=CARTESIAN_POINT('',(-16.1691588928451,2.60884516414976,24.7915588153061));
#1499=CARTESIAN_POINT('',(-16.2067663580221,2.60780469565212,25.254174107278));
#1500=CARTESIAN_POINT('',(-16.2585447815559,2.60640291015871,25.5604124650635));
#1501=CARTESIAN_POINT('',(-16.4086777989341,2.60419294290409,26.1623826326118));
#1502=CARTESIAN_POINT('',(-16.507274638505,2.60338790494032,26.4580510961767));
#1503=CARTESIAN_POINT('',(-16.7113723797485,2.60518732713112,26.9626322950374));
#1504=CARTESIAN_POINT('',(-16.8090508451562,2.60699326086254,27.1748260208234));
#1505=CARTESIAN_POINT('',(-17.0197513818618,2.61383210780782,27.5889785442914));
#1506=CARTESIAN_POINT('',(-17.1326231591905,2.6188350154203,27.7910138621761));
#1507=CARTESIAN_POINT('',(-17.2515916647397,2.62601624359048,27.9890614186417));
#1508=B_SPLINE_CURVE_WITH_KNOTS('',3,(#1484,#1485,#1486,#1487,#1488,#1489,#1490,#1491,#1492,
#1493,#1494,#1495,#1496,#1497,#1498,#1499,#1500,#1501,#1502,#1503,#1504,#1505,#1506,#1507),
.UNSPECIFIED.,.F.,.F.,(4,2,2,2,2,2,2,2,2,2,2,4),(0.,0.560608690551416,1.12246406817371,
2.25597729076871,2.72334272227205,3.1904631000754,3.65501542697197,4.11957506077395,
5.04670400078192,5.9786832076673,6.67876235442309,7.37236544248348),.UNSPECIFIED.);
#1509=CARTESIAN_POINT('',(-17.2513916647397,2.62600423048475,27.9887286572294));
#1510=VERTEX_POINT('',#1509);
#1511=EDGE_CURVE('E33',#1481,#1510,#1508,.T.);
#1512=ORIENTED_EDGE('',*,*,#1511,.T.);
#1513=EDGE_CURVE('E148',#1510,#659,#1479,.T.);
#1514=ORIENTED_EDGE('',*,*,#1513,.T.);
#1515=ORIENTED_EDGE('',*,*,#837,.F.);
#1516=ORIENTED_EDGE('',*,*,#943,.F.);
#1517=ORIENTED_EDGE('',*,*,#119,.F.);
#1518=ORIENTED_EDGE('',*,*,#262,.T.);
#1519=EDGE_LOOP('',(#1483,#1512,#1514,#1515,#1516,#1517,#1518));
#1520=FACE_BOUND('',#1519,.T.);
#1521=ADVANCED_FACE('F147',(#1520),#1475,.F.);
#1522=CARTESIAN_POINT('',(16.5160135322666,14.8706062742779,-6.26382242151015));
#1523=DIRECTION('',(0.,0.,1.));
#1524=DIRECTION('',(0.,-1.,0.));
#1525=AXIS2_PLACEMENT_3D('',#1522,#1523,#1524);
#1526=CYLINDRICAL_SURFACE('',#1525,12.2666645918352);
#1527=CARTESIAN_POINT('',(17.2515916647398,2.62601624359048,21.0372395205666));
#1528=CARTESIAN_POINT('',(17.155383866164,2.62022150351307,21.1974244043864));
#1529=CARTESIAN_POINT('',(17.0632330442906,2.61583941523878,21.3600342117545));
#1530=CARTESIAN_POINT('',(16.8887391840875,2.60929797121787,21.6909196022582));
#1531=CARTESIAN_POINT('',(16.8064184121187,2.60714358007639,21.8592069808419));
#1532=CARTESIAN_POINT('',(16.5760436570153,2.60311809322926,22.375715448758));
#1533=CARTESIAN_POINT('',(16.4463279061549,2.60376545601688,22.7327987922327));
#1534=CARTESIAN_POINT('',(16.3111238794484,2.60558962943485,23.2492659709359));
#1535=CARTESIAN_POINT('',(16.2774293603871,2.60623171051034,23.4015078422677));
#1536=CARTESIAN_POINT('',(16.2226438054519,2.60741948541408,23.7082136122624));
#1537=CARTESIAN_POINT('',(16.2015461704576,2.60796522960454,23.8626763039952));
#1538=CARTESIAN_POINT('',(16.1728384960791,2.60873412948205,24.1720064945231));
#1539=CARTESIAN_POINT('',(16.1651549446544,2.60895904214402,24.3268670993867));
#1540=CARTESIAN_POINT('',(16.1633150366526,2.60901456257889,24.6366432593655));
#1541=CARTESIAN_POINT('',(16.1691588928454,2.60884516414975,24.7915588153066));
#1542=CARTESIAN_POINT('',(16.2067663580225,2.60780469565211,25.2541741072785));
#1543=CARTESIAN_POINT('',(16.2585447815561,2.60640291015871,25.560412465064));
#1544=CARTESIAN_POINT('',(16.4086777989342,2.60419294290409,26.1623826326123));
#1545=CARTESIAN_POINT('',(16.5072746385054,2.60338790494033,26.4580510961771));
#1546=CARTESIAN_POINT('',(16.711372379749,2.60518732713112,26.9626322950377));
#1547=CARTESIAN_POINT('',(16.8090508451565,2.60699326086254,27.1748260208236));
#1548=CARTESIAN_POINT('',(17.0197513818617,2.61383210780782,27.5889785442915));
#1549=CARTESIAN_POINT('',(17.1326231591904,2.61883501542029,27.7910138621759));
#1550=CARTESIAN_POINT('',(17.2515916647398,2.62601624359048,27.9890614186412));
#1551=B_SPLINE_CURVE_WITH_KNOTS('',3,(#1527,#1528,#1529,#1530,#1531,#1532,#1533,#1534,#1535,
#1536,#1537,#1538,#1539,#1540,#1541,#1542,#1543,#1544,#1545,#1546,#1547,#1548,#1549,#1550),
.UNSPECIFIED.,.F.,.F.,(4,2,2,2,2,2,2,2,2,2,2,4),(0.,0.560608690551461,1.12246406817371,
2.25597729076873,2.7233427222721,3.19046310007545,3.65501542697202,4.11957506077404,
5.046704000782,5.97868320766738,6.67876235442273,7.37236544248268),.UNSPECIFIED.);
#1552=CARTESIAN_POINT('',(17.2513916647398,2.62600423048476,21.0375722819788));
#1553=VERTEX_POINT('',#1552);
#1554=CARTESIAN_POINT('',(17.2513916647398,2.62600423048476,27.988728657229));
#1555=VERTEX_POINT('',#1554);
#1556=EDGE_CURVE('E223',#1553,#1555,#1551,.T.);
#1557=ORIENTED_EDGE('',*,*,#1556,.F.);
#1558=DIRECTION('',(0.,0.,1.));
#1559=VECTOR('',#1558,1.);
#1560=CARTESIAN_POINT('',(17.2513916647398,2.62600423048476,-6.26382242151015));
#1561=LINE('',#1560,#1559);
#1562=EDGE_CURVE('E237',#1099,#1553,#1561,.T.);
#1563=ORIENTED_EDGE('',*,*,#1562,.F.);
#1564=ORIENTED_EDGE('',*,*,#1100,.F.);
#1565=ORIENTED_EDGE('',*,*,#1009,.T.);
#1566=ORIENTED_EDGE('',*,*,#952,.T.);
#1567=ORIENTED_EDGE('',*,*,#801,.T.);
#1568=EDGE_CURVE('E236',#1555,#771,#1561,.T.);
#1569=ORIENTED_EDGE('',*,*,#1568,.F.);
#1570=EDGE_LOOP('',(#1557,#1563,#1564,#1565,#1566,#1567,#1569));
#1571=FACE_BOUND('',#1570,.T.);
#1572=ADVANCED_FACE('F245',(#1571),#1526,.F.);
#1573=CARTESIAN_POINT('',(-10.2946161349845,118.46157794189,-6.26382242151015));
#1574=DIRECTION('',(0.,0.,1.));
#1575=DIRECTION('',(0.,-1.,0.));
#1576=AXIS2_PLACEMENT_3D('',#1573,#1574,#1575);
#1577=CYLINDRICAL_SURFACE('',#1576,116.044288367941);
#1578=CARTESIAN_POINT('',(-17.2511916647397,2.6259922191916,21.0379050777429));
#1579=CARTESIAN_POINT('',(-17.3605509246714,2.63256021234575,20.8558730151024));
#1580=CARTESIAN_POINT('',(-17.478176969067,2.63977928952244,20.6788860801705));
#1581=CARTESIAN_POINT('',(-17.728589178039,2.65558215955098,20.3361701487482));
#1582=CARTESIAN_POINT('',(-17.8613680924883,2.66416530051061,20.1704358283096));
#1583=CARTESIAN_POINT('',(-18.1403342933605,2.68273269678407,19.8517713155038));
#1584=CARTESIAN_POINT('',(-18.2864734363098,2.69271198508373,19.6987986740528));
#1585=CARTESIAN_POINT('',(-18.5911387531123,2.71414613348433,19.405903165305));
#1586=CARTESIAN_POINT('',(-18.7496661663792,2.72560114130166,19.2659816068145));
#1587=CARTESIAN_POINT('',(-19.241270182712,2.76221931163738,18.8673844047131));
#1588=CARTESIAN_POINT('',(-19.5910610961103,2.78968031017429,18.6290924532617));
#1589=CARTESIAN_POINT('',(-20.3238326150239,2.85090757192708,18.2118100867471));
#1590=CARTESIAN_POINT('',(-20.7068386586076,2.88467869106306,18.0328656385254));
#1591=CARTESIAN_POINT('',(-21.5122385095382,2.9600110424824,17.7306832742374));
#1592=CARTESIAN_POINT('',(-21.9356131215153,3.00184137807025,17.6101220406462));
#1593=CARTESIAN_POINT('',(-22.7954871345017,3.09177206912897,17.4380525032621));
#1594=CARTESIAN_POINT('',(-23.2319888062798,3.13987351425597,17.3865562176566));
#1595=CARTESIAN_POINT('',(-24.1298090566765,3.24404995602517,17.3524127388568));
#1596=CARTESIAN_POINT('',(-24.5912401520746,3.3004091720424,17.3734764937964));
#1597=CARTESIAN_POINT('',(-25.5036209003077,3.41734859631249,17.4924935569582));
#1598=CARTESIAN_POINT('',(-25.95456894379,3.47792944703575,17.5904585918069));
#1599=CARTESIAN_POINT('',(-26.836089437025,3.60141943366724,17.8628288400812));
#1600=CARTESIAN_POINT('',(-27.2664963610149,3.66434194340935,18.0377665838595));
#1601=CARTESIAN_POINT('',(-28.0897613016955,3.78907433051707,18.4612298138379));
#1602=CARTESIAN_POINT('',(-28.4826254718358,3.85088438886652,18.7097432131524));
#1603=CARTESIAN_POINT('',(-29.2009277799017,3.96723220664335,19.2630368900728));
#1604=CARTESIAN_POINT('',(-29.5285296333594,4.02196785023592,19.564959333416));
#1605=CARTESIAN_POINT('',(-30.1237087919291,4.12359078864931,20.2242762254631));
#1606=CARTESIAN_POINT('',(-30.3913170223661,4.17048212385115,20.5816419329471));
#1607=CARTESIAN_POINT('',(-30.8373181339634,4.24983645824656,21.3128397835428));
#1608=CARTESIAN_POINT('',(-31.0209063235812,4.28311924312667,21.6834132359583));
#1609=CARTESIAN_POINT('',(-31.3188213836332,4.33759779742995,22.4522485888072));
#1610=CARTESIAN_POINT('',(-31.4331834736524,4.35879971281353,22.8504962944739));
#1611=CARTESIAN_POINT('',(-31.5819417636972,4.38646265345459,23.6329821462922));
#1612=CARTESIAN_POINT('',(-31.6214051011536,4.39385715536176,24.016229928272));
#1613=CARTESIAN_POINT('',(-31.6343122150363,4.39627063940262,24.7838358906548));
#1614=CARTESIAN_POINT('',(-31.6077711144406,4.39129245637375,25.1681937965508));
#1615=CARTESIAN_POINT('',(-31.4916539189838,4.36966021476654,25.9147246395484));
#1616=CARTESIAN_POINT('',(-31.4040395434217,4.35336958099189,26.2772163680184));
#1617=CARTESIAN_POINT('',(-31.171301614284,4.31056061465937,26.9825464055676));
#1618=CARTESIAN_POINT('',(-31.0261753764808,4.28404180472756,27.3253837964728));
#1619=CARTESIAN_POINT('',(-30.6801290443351,4.22174644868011,27.9896317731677));
#1620=CARTESIAN_POINT('',(-30.4781308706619,4.18579203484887,28.3104623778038));
#1621=CARTESIAN_POINT('',(-30.0265224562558,4.10694895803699,28.915621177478));
#1622=CARTESIAN_POINT('',(-29.7769013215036,4.06405870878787,29.1999409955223));
#1623=CARTESIAN_POINT('',(-29.2214742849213,3.97081569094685,29.7422665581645));
#1624=CARTESIAN_POINT('',(-28.9132096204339,3.92017079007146,29.9977012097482));
#1625=CARTESIAN_POINT('',(-28.2607761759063,3.8160237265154,30.4568418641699));
#1626=CARTESIAN_POINT('',(-27.9165957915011,3.76252064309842,30.6605310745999));
#1627=CARTESIAN_POINT('',(-27.1748146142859,3.65092338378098,31.0261640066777));
#1628=CARTESIAN_POINT('',(-26.7751452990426,3.59278264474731,31.1838989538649));
#1629=CARTESIAN_POINT('',(-25.9555667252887,3.47817566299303,31.4338219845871));
#1630=CARTESIAN_POINT('',(-25.5356510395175,3.42170996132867,31.5259891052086));
#1631=CARTESIAN_POINT('',(-24.6605018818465,3.30905170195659,31.6471280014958));
#1632=CARTESIAN_POINT('',(-24.2046656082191,3.25308093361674,31.6719539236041));
#1633=CARTESIAN_POINT('',(-23.2941812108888,3.14680042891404,31.6461183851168));
#1634=CARTESIAN_POINT('',(-22.839533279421,3.09649155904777,31.5954453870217));
#1635=CARTESIAN_POINT('',(-22.1635402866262,3.025626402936,31.4625458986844));
#1636=CARTESIAN_POINT('',(-21.9367328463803,3.00254244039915,31.4078302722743));
#1637=CARTESIAN_POINT('',(-21.4884958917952,2.95822534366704,31.2791261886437));
#1638=CARTESIAN_POINT('',(-21.2670643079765,2.9369914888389,31.2051452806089));
#1639=CARTESIAN_POINT('',(-20.8311241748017,2.89641504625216,31.0381373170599));
#1640=CARTESIAN_POINT('',(-20.6166214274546,2.87707401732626,30.9450947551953));
#1641=CARTESIAN_POINT('',(-20.1965861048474,2.84033307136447,30.7404574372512));
#1642=CARTESIAN_POINT('',(-19.9910494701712,2.82293227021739,30.6288711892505));
#1643=CARTESIAN_POINT('',(-19.5960776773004,2.79050166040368,30.3909216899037));
#1644=CARTESIAN_POINT('',(-19.406357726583,2.77542055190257,30.2650383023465));
#1645=CARTESIAN_POINT('',(-19.0388353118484,2.74706092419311,29.9969053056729));
#1646=CARTESIAN_POINT('',(-18.8610271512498,2.73378154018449,29.8546636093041));
#1647=CARTESIAN_POINT('',(-18.5192661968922,2.70899133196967,29.5548548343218));
#1648=CARTESIAN_POINT('',(-18.3552890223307,2.69747736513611,29.3973158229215));
#1649=CARTESIAN_POINT('',(-18.0426182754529,2.67613037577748,29.0677691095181));
#1650=CARTESIAN_POINT('',(-17.8939151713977,2.66629630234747,28.8957705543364));
#1651=CARTESIAN_POINT('',(-17.6624475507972,2.65138715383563,28.6009730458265));
#1652=CARTESIAN_POINT('',(-17.5748056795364,2.64585026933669,28.4819960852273));
#1653=CARTESIAN_POINT('',(-17.4071874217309,2.63543572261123,28.2389515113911));
#1654=CARTESIAN_POINT('',(-17.3272016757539,2.63055725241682,28.114890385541));
#1655=CARTESIAN_POINT('',(-17.2511916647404,2.62599221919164,27.9883958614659));
#1656=B_SPLINE_CURVE_WITH_KNOTS('',3,(#1578,#1579,#1580,#1581,#1582,#1583,#1584,#1585,#1586,
#1587,#1588,#1589,#1590,#1591,#1592,#1593,#1594,#1595,#1596,#1597,#1598,#1599,#1600,#1601,#1602,
#1603,#1604,#1605,#1606,#1607,#1608,#1609,#1610,#1611,#1612,#1613,#1614,#1615,#1616,#1617,#1618,
#1619,#1620,#1621,#1622,#1623,#1624,#1625,#1626,#1627,#1628,#1629,#1630,#1631,#1632,#1633,#1634,
#1635,#1636,#1637,#1638,#1639,#1640,#1641,#1642,#1643,#1644,#1645,#1646,#1647,#1648,#1649,#1650,
#1651,#1652,#1653,#1654,#1655),.UNSPECIFIED.,.F.,.F.,(4,2,2,2,2,2,2,2,2,2,2,2,2,2,2,2,2,2,2,2,2,
2,2,2,2,2,2,2,2,2,2,2,2,2,2,2,2,2,4),(0.,0.637081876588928,1.27386019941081,1.90842811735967,
2.54305960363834,3.80922160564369,5.07636201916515,6.3971044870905,7.71807675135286,
9.1075891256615,10.4973134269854,11.8968074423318,13.2960716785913,14.6355489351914,
15.9743341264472,17.2124522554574,18.4499399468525,19.6002244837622,20.7502454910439,
21.8649336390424,22.9796738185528,24.1171609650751,25.2549086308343,26.460330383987,
27.6661428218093,28.9612559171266,30.2567828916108,31.6304309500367,33.004288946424,
33.7069364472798,34.409309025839,35.1122552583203,35.8148798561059,36.4985491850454,
37.1818891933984,37.863998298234,38.5456791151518,38.989039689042,39.4318511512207),.UNSPECIFIED.);
#1657=EDGE_CURVE('E9',#1481,#1510,#1656,.T.);
#1658=ORIENTED_EDGE('',*,*,#1657,.F.);
#1659=ORIENTED_EDGE('',*,*,#1482,.F.);
#1660=ORIENTED_EDGE('',*,*,#223,.F.);
#1661=ORIENTED_EDGE('',*,*,#451,.F.);
#1662=ORIENTED_EDGE('',*,*,#660,.T.);
#1663=ORIENTED_EDGE('',*,*,#1513,.F.);
#1664=EDGE_LOOP('',(#1658,#1659,#1660,#1661,#1662,#1663));
#1665=FACE_BOUND('',#1664,.T.);
#1666=ADVANCED_FACE('F152',(#1665),#1577,.F.);
#1667=CARTESIAN_POINT('',(10.2946161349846,118.46157794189,-6.26382242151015));
#1668=DIRECTION('',(0.,0.,1.));
#1669=DIRECTION('',(0.,-1.,0.));
#1670=AXIS2_PLACEMENT_3D('',#1667,#1668,#1669);
#1671=CYLINDRICAL_SURFACE('',#1670,116.044288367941);
#1672=ORIENTED_EDGE('',*,*,#1562,.T.);
#1673=CARTESIAN_POINT('',(17.2511916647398,2.6259922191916,21.0379050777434));
#1674=CARTESIAN_POINT('',(17.3605509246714,2.63256021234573,20.8558730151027));
#1675=CARTESIAN_POINT('',(17.4781769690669,2.63977928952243,20.6788860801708));
#1676=CARTESIAN_POINT('',(17.7285891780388,2.65558215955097,20.3361701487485));
#1677=CARTESIAN_POINT('',(17.8613680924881,2.6641653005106,20.1704358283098));
#1678=CARTESIAN_POINT('',(18.1403342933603,2.68273269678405,19.851771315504));
#1679=CARTESIAN_POINT('',(18.2864734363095,2.6927119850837,19.698798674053));
#1680=CARTESIAN_POINT('',(18.5911387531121,2.7141461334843,19.4059031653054));
#1681=CARTESIAN_POINT('',(18.7496661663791,2.72560114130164,19.265981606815));
#1682=CARTESIAN_POINT('',(19.241270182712,2.76221931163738,18.8673844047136));
#1683=CARTESIAN_POINT('',(19.5910610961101,2.78968031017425,18.629092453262));
#1684=CARTESIAN_POINT('',(20.3238326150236,2.85090757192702,18.2118100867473));
#1685=CARTESIAN_POINT('',(20.7068386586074,2.88467869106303,18.0328656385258));
#1686=CARTESIAN_POINT('',(21.512238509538,2.96001104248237,17.7306832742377));
#1687=CARTESIAN_POINT('',(21.935613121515,3.0018413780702,17.6101220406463));
#1688=CARTESIAN_POINT('',(22.7954871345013,3.09177206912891,17.4380525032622));
#1689=CARTESIAN_POINT('',(23.2319888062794,3.13987351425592,17.3865562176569));
#1690=CARTESIAN_POINT('',(24.129809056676,3.24404995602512,17.352412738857));
#1691=CARTESIAN_POINT('',(24.5912401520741,3.30040917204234,17.3734764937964));
#1692=CARTESIAN_POINT('',(25.5036209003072,3.4173485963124,17.4924935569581));
#1693=CARTESIAN_POINT('',(25.9545689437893,3.47792944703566,17.5904585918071));
#1694=CARTESIAN_POINT('',(26.8360894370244,3.60141943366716,17.8628288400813));
#1695=CARTESIAN_POINT('',(27.2664963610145,3.66434194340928,18.0377665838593));
#1696=CARTESIAN_POINT('',(28.0897613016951,3.78907433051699,18.4612298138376));
#1697=CARTESIAN_POINT('',(28.4826254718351,3.8508843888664,18.7097432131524));
#1698=CARTESIAN_POINT('',(29.2009277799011,3.96723220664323,19.2630368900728));
#1699=CARTESIAN_POINT('',(29.5285296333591,4.02196785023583,19.5649593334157));
#1700=CARTESIAN_POINT('',(30.1237087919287,4.12359078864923,20.2242762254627));
#1701=CARTESIAN_POINT('',(30.3913170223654,4.17048212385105,20.5816419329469));
#1702=CARTESIAN_POINT('',(30.8373181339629,4.24983645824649,21.3128397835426));
#1703=CARTESIAN_POINT('',(31.020906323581,4.28311924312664,21.6834132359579));
#1704=CARTESIAN_POINT('',(31.318821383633,4.3375977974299,22.4522485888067));
#1705=CARTESIAN_POINT('',(31.4331834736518,4.35879971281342,22.8504962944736));
#1706=CARTESIAN_POINT('',(31.5819417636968,4.38646265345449,23.6329821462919));
#1707=CARTESIAN_POINT('',(31.6214051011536,4.39385715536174,24.0162299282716));
#1708=CARTESIAN_POINT('',(31.6343122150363,4.39627063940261,24.7838358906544));
#1709=CARTESIAN_POINT('',(31.6077711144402,4.39129245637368,25.1681937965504));
#1710=CARTESIAN_POINT('',(31.4916539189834,4.36966021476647,25.914724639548));
#1711=CARTESIAN_POINT('',(31.4040395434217,4.35336958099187,26.2772163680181));
#1712=CARTESIAN_POINT('',(31.1713016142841,4.31056061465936,26.9825464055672));
#1713=CARTESIAN_POINT('',(31.0261753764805,4.28404180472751,27.3253837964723));
#1714=CARTESIAN_POINT('',(30.6801290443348,4.22174644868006,27.9896317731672));
#1715=CARTESIAN_POINT('',(30.478130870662,4.18579203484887,28.3104623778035));
#1716=CARTESIAN_POINT('',(30.026522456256,4.10694895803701,28.9156211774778));
#1717=CARTESIAN_POINT('',(29.7769013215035,4.06405870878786,29.1999409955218));
#1718=CARTESIAN_POINT('',(29.2214742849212,3.97081569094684,29.742266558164));
#1719=CARTESIAN_POINT('',(28.913209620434,3.92017079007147,29.997701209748));
#1720=CARTESIAN_POINT('',(28.2607761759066,3.81602372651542,30.4568418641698));
#1721=CARTESIAN_POINT('',(27.9165957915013,3.76252064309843,30.6605310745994));
#1722=CARTESIAN_POINT('',(27.174814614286,3.65092338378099,31.0261640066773));
#1723=CARTESIAN_POINT('',(26.7751452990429,3.59278264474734,31.1838989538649));
#1724=CARTESIAN_POINT('',(25.955566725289,3.47817566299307,31.4338219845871));
#1725=CARTESIAN_POINT('',(25.5356510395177,3.4217099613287,31.5259891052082));
#1726=CARTESIAN_POINT('',(24.6605018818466,3.30905170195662,31.6471280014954));
#1727=CARTESIAN_POINT('',(24.2046656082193,3.25308093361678,31.6719539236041));
#1728=CARTESIAN_POINT('',(23.2941812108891,3.14680042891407,31.6461183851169));
#1729=CARTESIAN_POINT('',(22.8395332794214,3.09649155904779,31.5954453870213));
#1730=CARTESIAN_POINT('',(22.1635402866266,3.02562640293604,31.4625458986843));
#1731=CARTESIAN_POINT('',(21.9367328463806,3.00254244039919,31.4078302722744));
#1732=CARTESIAN_POINT('',(21.4884958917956,2.95822534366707,31.2791261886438));
#1733=CARTESIAN_POINT('',(21.267064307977,2.93699148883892,31.205145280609));
#1734=CARTESIAN_POINT('',(20.8311241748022,2.89641504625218,31.03813731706));
#1735=CARTESIAN_POINT('',(20.616621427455,2.87707401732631,30.9450947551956));
#1736=CARTESIAN_POINT('',(20.1965861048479,2.84033307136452,30.7404574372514));
#1737=CARTESIAN_POINT('',(19.9910494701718,2.82293227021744,30.6288711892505));
#1738=CARTESIAN_POINT('',(19.596077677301,2.7905016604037,30.3909216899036));
#1739=CARTESIAN_POINT('',(19.4063577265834,2.77542055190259,30.2650383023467));
#1740=CARTESIAN_POINT('',(19.0388353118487,2.74706092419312,29.9969053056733));
#1741=CARTESIAN_POINT('',(18.8610271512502,2.73378154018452,29.8546636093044));
#1742=CARTESIAN_POINT('',(18.5192661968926,2.70899133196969,29.5548548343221));
#1743=CARTESIAN_POINT('',(18.355289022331,2.69747736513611,29.3973158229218));
#1744=CARTESIAN_POINT('',(18.0426182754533,2.67613037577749,29.0677691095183));
#1745=CARTESIAN_POINT('',(17.8939151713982,2.6662963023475,28.8957705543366));
#1746=CARTESIAN_POINT('',(17.6624475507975,2.65138715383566,28.6009730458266));
#1747=CARTESIAN_POINT('',(17.5748056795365,2.64585026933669,28.4819960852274));
#1748=CARTESIAN_POINT('',(17.4071874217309,2.63543572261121,28.238951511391));
#1749=CARTESIAN_POINT('',(17.3272016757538,2.6305572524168,28.1148903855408));
#1750=CARTESIAN_POINT('',(17.2511916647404,2.62599221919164,27.9883958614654));
#1751=B_SPLINE_CURVE_WITH_KNOTS('',3,(#1673,#1674,#1675,#1676,#1677,#1678,#1679,#1680,#1681,
#1682,#1683,#1684,#1685,#1686,#1687,#1688,#1689,#1690,#1691,#1692,#1693,#1694,#1695,#1696,#1697,
#1698,#1699,#1700,#1701,#1702,#1703,#1704,#1705,#1706,#1707,#1708,#1709,#1710,#1711,#1712,#1713,
#1714,#1715,#1716,#1717,#1718,#1719,#1720,#1721,#1722,#1723,#1724,#1725,#1726,#1727,#1728,#1729,
#1730,#1731,#1732,#1733,#1734,#1735,#1736,#1737,#1738,#1739,#1740,#1741,#1742,#1743,#1744,#1745,
#1746,#1747,#1748,#1749,#1750),.UNSPECIFIED.,.F.,.F.,(4,2,2,2,2,2,2,2,2,2,2,2,2,2,2,2,2,2,2,2,2,
2,2,2,2,2,2,2,2,2,2,2,2,2,2,2,2,2,4),(0.,0.63708187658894,1.27386019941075,1.90842811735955,
2.54305960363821,3.80922160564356,5.07636201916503,6.39710448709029,7.71807675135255,
9.10758912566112,10.497313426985,11.8968074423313,13.2960716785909,14.6355489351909,
15.9743341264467,17.2124522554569,18.449939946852,19.6002244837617,20.7502454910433,
21.8649336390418,22.9796738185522,24.1171609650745,25.2549086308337,26.4603303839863,
27.6661428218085,28.9612559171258,30.2567828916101,31.630430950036,33.0042889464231,
33.7069364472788,34.4093090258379,35.1122552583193,35.8148798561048,36.4985491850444,
37.1818891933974,37.863998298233,38.5456791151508,38.9890396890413,39.4318511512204),.UNSPECIFIED.);
#1752=EDGE_CURVE('E364',#1553,#1555,#1751,.T.);
#1753=ORIENTED_EDGE('',*,*,#1752,.T.);
#1754=ORIENTED_EDGE('',*,*,#1568,.T.);
#1755=ORIENTED_EDGE('',*,*,#772,.F.);
#1756=ORIENTED_EDGE('',*,*,#544,.T.);
#1757=ORIENTED_EDGE('',*,*,#1117,.T.);
#1758=EDGE_LOOP('',(#1672,#1753,#1754,#1755,#1756,#1757));
#1759=FACE_BOUND('',#1758,.T.);
#1760=ADVANCED_FACE('F282',(#1759),#1671,.F.);
#1761=CARTESIAN_POINT('',(21.9908821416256,-20.,24.5131504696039));
#1762=DIRECTION('',(0.,-1.,0.));
#1763=DIRECTION('',(1.,0.,0.));
#1764=AXIS2_PLACEMENT_3D('',#1761,#1762,#1763);
#1765=SPHERICAL_SURFACE('',#1764,18.3411597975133);
#1766=ORIENTED_EDGE('',*,*,#1461,.T.);
#1767=ORIENTED_EDGE('',*,*,#1366,.F.);
#1768=EDGE_LOOP('',(#1766,#1767));
#1769=FACE_BOUND('',#1768,.T.);
#1770=ADVANCED_FACE('F196',(#1769),#1765,.F.);
#1771=CARTESIAN_POINT('',(21.9908821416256,20.,24.5131504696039));
#1772=DIRECTION('',(0.,1.,0.));
#1773=DIRECTION('',(1.,0.,0.));
#1774=AXIS2_PLACEMENT_3D('',#1771,#1772,#1773);
#1775=SPHERICAL_SURFACE('',#1774,18.3411597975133);
#1776=ORIENTED_EDGE('',*,*,#1556,.T.);
#1777=ORIENTED_EDGE('',*,*,#1752,.F.);
#1778=EDGE_LOOP('',(#1776,#1777));
#1779=FACE_BOUND('',#1778,.T.);
#1780=ADVANCED_FACE('F375',(#1779),#1775,.F.);
#1781=CARTESIAN_POINT('',(-21.9908821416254,-20.,24.5131504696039));
#1782=DIRECTION('',(0.,-1.,0.));
#1783=DIRECTION('',(-1.,0.,0.));
#1784=AXIS2_PLACEMENT_3D('',#1781,#1782,#1783);
#1785=SPHERICAL_SURFACE('',#1784,18.3411597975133);
#1786=ORIENTED_EDGE('',*,*,#1315,.T.);
#1787=ORIENTED_EDGE('',*,*,#1275,.F.);
#1788=EDGE_LOOP('',(#1786,#1787));
#1789=FACE_BOUND('',#1788,.T.);
#1790=ADVANCED_FACE('F378',(#1789),#1785,.F.);
#1791=CARTESIAN_POINT('',(-21.9908821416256,20.,24.5131504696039));
#1792=DIRECTION('',(0.,1.,0.));
#1793=DIRECTION('',(-1.,0.,0.));
#1794=AXIS2_PLACEMENT_3D('',#1791,#1792,#1793);
#1795=SPHERICAL_SURFACE('',#1794,18.3411597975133);
#1796=ORIENTED_EDGE('',*,*,#1657,.T.);
#1797=ORIENTED_EDGE('',*,*,#1511,.F.);
#1798=EDGE_LOOP('',(#1796,#1797));
#1799=FACE_BOUND('',#1798,.T.);
#1800=ADVANCED_FACE('F141',(#1799),#1795,.F.);
#1801=CLOSED_SHELL('',(#130,#266,#456,#641,#852,#866,#883,#903,#923,#967,#1059,#1180,#1284,
#1325,#1376,#1470,#1521,#1572,#1666,#1760,#1770,#1780,#1790,#1800));
#1802=MANIFOLD_SOLID_BREP('B1',#1801);
#1803=ADVANCED_BREP_SHAPE_REPRESENTATION('',(#18,#1802),#14);
#1804=SHAPE_DEFINITION_REPRESENTATION(#9,#1803);
ENDSEC;
END-ISO-10303-21;
